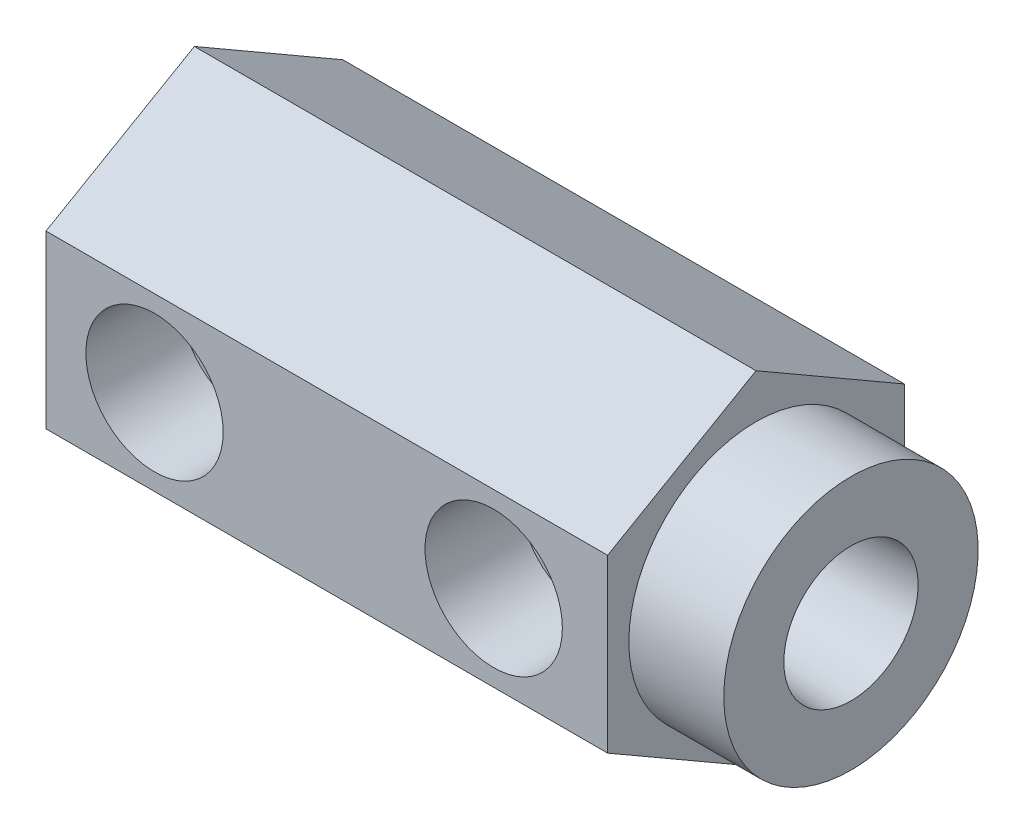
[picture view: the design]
ISO-10303-21;
HEADER;
FILE_DESCRIPTION(('STEP AP214'),'2;1');
FILE_NAME('part.step','',(''),(''),'','','');
FILE_SCHEMA(('AUTOMOTIVE_DESIGN { 1 0 10303 214 1 1 1 1 }'));
ENDSEC;
DATA;
#1=APPLICATION_CONTEXT('core data for automotive mechanical design processes');
#2=APPLICATION_PROTOCOL_DEFINITION('international standard','automotive_design',2000,#1);
#3=PRODUCT_CONTEXT('',#1,'mechanical');
#4=PRODUCT('Part','Part','',(#3));
#5=PRODUCT_RELATED_PRODUCT_CATEGORY('part','',(#4));
#6=PRODUCT_DEFINITION_FORMATION('','',#4);
#7=PRODUCT_DEFINITION_CONTEXT('part definition',#1,'design');
#8=PRODUCT_DEFINITION('design','',#6,#7);
#9=PRODUCT_DEFINITION_SHAPE('','',#8);
#10=(LENGTH_UNIT() NAMED_UNIT(*) SI_UNIT(.MILLI.,.METRE.));
#11=(NAMED_UNIT(*) PLANE_ANGLE_UNIT() SI_UNIT($,.RADIAN.));
#12=(NAMED_UNIT(*) SI_UNIT($,.STERADIAN.) SOLID_ANGLE_UNIT());
#13=UNCERTAINTY_MEASURE_WITH_UNIT(LENGTH_MEASURE(1.E-05),#10,'distance_accuracy_value','');
#14=(GEOMETRIC_REPRESENTATION_CONTEXT(3) GLOBAL_UNCERTAINTY_ASSIGNED_CONTEXT((#13)) GLOBAL_UNIT_ASSIGNED_CONTEXT((#10,
#11,#12)) REPRESENTATION_CONTEXT('',''));
#15=CARTESIAN_POINT('',(0.,0.,0.));
#16=DIRECTION('',(0.,0.,1.));
#17=DIRECTION('',(1.,0.,0.));
#18=AXIS2_PLACEMENT_3D('',#15,#16,#17);
#19=CARTESIAN_POINT('',(49.1744,0.,0.));
#20=DIRECTION('',(-1.,0.,0.));
#21=DIRECTION('',(0.,0.,1.));
#22=AXIS2_PLACEMENT_3D('',#19,#20,#21);
#23=PLANE('',#22);
#24=CARTESIAN_POINT('',(49.1744,0.,0.));
#25=DIRECTION('',(-1.,0.,0.));
#26=DIRECTION('',(0.,0.,1.));
#27=AXIS2_PLACEMENT_3D('',#24,#25,#26);
#28=CIRCLE('',#27,9.525);
#29=CARTESIAN_POINT('',(49.1744,0.,9.525));
#30=VERTEX_POINT('',#29);
#31=EDGE_CURVE('E165',#30,#30,#28,.T.);
#32=ORIENTED_EDGE('',*,*,#31,.F.);
#33=EDGE_LOOP('',(#32));
#34=FACE_BOUND('',#33,.T.);
#35=CARTESIAN_POINT('',(49.1744,0.,0.));
#36=DIRECTION('',(-1.,0.,0.));
#37=DIRECTION('',(0.,0.,1.));
#38=AXIS2_PLACEMENT_3D('',#35,#36,#37);
#39=CIRCLE('',#38,5.0292);
#40=CARTESIAN_POINT('',(49.1744,0.,5.0292));
#41=VERTEX_POINT('',#40);
#42=EDGE_CURVE('E256',#41,#41,#39,.T.);
#43=ORIENTED_EDGE('',*,*,#42,.T.);
#44=EDGE_LOOP('',(#43));
#45=FACE_BOUND('',#44,.T.);
#46=ADVANCED_FACE('F35',(#34,#45),#23,.F.);
#47=CARTESIAN_POINT('',(33.528,0.,11.1125));
#48=DIRECTION('',(0.,0.,1.));
#49=DIRECTION('',(1.,0.,0.));
#50=AXIS2_PLACEMENT_3D('',#47,#48,#49);
#51=CYLINDRICAL_SURFACE('',#50,4.2164);
#52=CARTESIAN_POINT('',(37.5572446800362,1.24226256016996,4.18846));
#53=CARTESIAN_POINT('',(37.5231998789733,1.35273524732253,4.15571145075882));
#54=CARTESIAN_POINT('',(37.4849506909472,1.46061657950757,4.11894514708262));
#55=CARTESIAN_POINT('',(37.4010204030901,1.67046449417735,4.03838194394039));
#56=CARTESIAN_POINT('',(37.3553534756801,1.77244186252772,3.99459845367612));
#57=CARTESIAN_POINT('',(37.2579636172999,1.96909195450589,3.90138657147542));
#58=CARTESIAN_POINT('',(37.2063122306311,2.06383226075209,3.85202501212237));
#59=CARTESIAN_POINT('',(37.0973370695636,2.24704879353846,3.74810382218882));
#60=CARTESIAN_POINT('',(37.040010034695,2.33552136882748,3.69354120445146));
#61=CARTESIAN_POINT('',(36.9057433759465,2.52699524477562,3.56608812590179));
#62=CARTESIAN_POINT('',(36.8274426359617,2.62823562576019,3.49198535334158));
#63=CARTESIAN_POINT('',(36.6643644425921,2.82084714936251,3.33832581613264));
#64=CARTESIAN_POINT('',(36.5795859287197,2.91221667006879,3.25876815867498));
#65=CARTESIAN_POINT('',(36.4040104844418,3.08575940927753,3.09496594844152));
#66=CARTESIAN_POINT('',(36.313183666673,3.16788058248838,3.01069851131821));
#67=CARTESIAN_POINT('',(36.1266289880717,3.32262611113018,2.83900033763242));
#68=CARTESIAN_POINT('',(36.0309017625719,3.39525169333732,2.75157001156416));
#69=CARTESIAN_POINT('',(35.8327510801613,3.53285031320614,2.57262594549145));
#70=CARTESIAN_POINT('',(35.7302251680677,3.59761324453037,2.48106457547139));
#71=CARTESIAN_POINT('',(35.5205770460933,3.7178327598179,2.29700025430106));
#72=CARTESIAN_POINT('',(35.413452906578,3.77328538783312,2.2044969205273));
#73=CARTESIAN_POINT('',(35.1946305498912,3.87490518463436,2.02052791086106));
#74=CARTESIAN_POINT('',(35.0829462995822,3.9210984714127,1.92906002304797));
#75=CARTESIAN_POINT('',(34.8537235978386,4.00442086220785,1.74949909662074));
#76=CARTESIAN_POINT('',(34.7361912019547,4.04155911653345,1.66140272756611));
#77=CARTESIAN_POINT('',(34.5288880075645,4.09683754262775,1.51866750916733));
#78=CARTESIAN_POINT('',(34.4412500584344,4.11734344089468,1.46186744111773));
#79=CARTESIAN_POINT('',(34.2602263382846,4.15335926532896,1.35613372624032));
#80=CARTESIAN_POINT('',(34.166846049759,4.16887387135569,1.30719273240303));
#81=CARTESIAN_POINT('',(34.0032271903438,4.19006857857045,1.23719318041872));
#82=CARTESIAN_POINT('',(33.9349286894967,4.19730703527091,1.21220489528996));
#83=CARTESIAN_POINT('',(33.7951867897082,4.20850549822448,1.17274151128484));
#84=CARTESIAN_POINT('',(33.7237554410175,4.21247707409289,1.15822933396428));
#85=CARTESIAN_POINT('',(33.5783648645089,4.21673052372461,1.14266473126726));
#86=CARTESIAN_POINT('',(33.5043857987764,4.21696850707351,1.14177241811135));
#87=CARTESIAN_POINT('',(33.3576831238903,4.21360126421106,1.15412545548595));
#88=CARTESIAN_POINT('',(33.2849618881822,4.20998943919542,1.16739508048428));
#89=CARTESIAN_POINT('',(33.1190041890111,4.19759986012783,1.21128529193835));
#90=CARTESIAN_POINT('',(33.0270782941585,4.187494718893,1.24623585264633));
#91=CARTESIAN_POINT('',(32.8490963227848,4.16236327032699,1.32777375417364));
#92=CARTESIAN_POINT('',(32.7630740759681,4.14731106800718,1.37442201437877));
#93=CARTESIAN_POINT('',(32.5528728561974,4.10412945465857,1.49961321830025));
#94=CARTESIAN_POINT('',(32.4317509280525,4.07325238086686,1.58224397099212));
#95=CARTESIAN_POINT('',(32.1964925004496,4.00252087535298,1.75355286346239));
#96=CARTESIAN_POINT('',(32.082370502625,3.96264855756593,1.8422428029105));
#97=CARTESIAN_POINT('',(31.8591995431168,3.87396052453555,2.02210861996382));
#98=CARTESIAN_POINT('',(31.7501633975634,3.8251236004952,2.11328994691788));
#99=CARTESIAN_POINT('',(31.5367944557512,3.71851194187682,2.29570274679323));
#100=CARTESIAN_POINT('',(31.4324577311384,3.66074485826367,2.38693411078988));
#101=CARTESIAN_POINT('',(31.2217376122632,3.5320493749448,2.57385350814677));
#102=CARTESIAN_POINT('',(31.1156451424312,3.46051807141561,2.66945656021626));
#103=CARTESIAN_POINT('',(30.9087479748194,3.30668578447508,2.85780367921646));
#104=CARTESIAN_POINT('',(30.8079452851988,3.22438075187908,2.95054665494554));
#105=CARTESIAN_POINT('',(30.6125764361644,3.04885609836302,3.13157084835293));
#106=CARTESIAN_POINT('',(30.5179955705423,2.95566377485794,3.21986246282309));
#107=CARTESIAN_POINT('',(30.3358368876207,2.7579369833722,3.39076686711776));
#108=CARTESIAN_POINT('',(30.248259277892,2.65340217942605,3.47337948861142));
#109=CARTESIAN_POINT('',(30.0468993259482,2.38706899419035,3.66401417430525));
#110=CARTESIAN_POINT('',(29.9372028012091,2.21943248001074,3.76846671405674));
#111=CARTESIAN_POINT('',(29.7890253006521,1.95153796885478,3.91000109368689));
#112=CARTESIAN_POINT('',(29.742405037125,1.85961524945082,3.95461240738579));
#113=CARTESIAN_POINT('',(29.6552306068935,1.67047982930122,4.03813946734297));
#114=CARTESIAN_POINT('',(29.6146718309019,1.57327122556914,4.07705954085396));
#115=CARTESIAN_POINT('',(29.5633807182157,1.43577933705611,4.12632709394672));
#116=CARTESIAN_POINT('',(29.5497360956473,1.3975361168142,4.13943898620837));
#117=CARTESIAN_POINT('',(29.5234701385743,1.32038947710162,4.16468855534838));
#118=CARTESIAN_POINT('',(29.510848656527,1.28148615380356,4.17682637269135));
#119=CARTESIAN_POINT('',(29.4987553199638,1.24226256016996,4.18846));
#120=B_SPLINE_CURVE_WITH_KNOTS('',3,(#52,#53,#54,#55,#56,#57,#58,#59,#60,#61,#62,#63,#64,#65,
#66,#67,#68,#69,#70,#71,#72,#73,#74,#75,#76,#77,#78,#79,#80,#81,#82,#83,#84,#85,#86,#87,#88,#89,
#90,#91,#92,#93,#94,#95,#96,#97,#98,#99,#100,#101,#102,#103,#104,#105,#106,#107,#108,#109,#110,
#111,#112,#113,#114,#115,#116,#117,#118,#119),.UNSPECIFIED.,.F.,.F.,(4,2,2,2,2,2,2,2,2,2,2,2,2,
2,2,2,2,2,2,2,2,2,2,2,2,2,2,2,2,2,2,2,2,4),(0.,0.360139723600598,0.719599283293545,
1.07513522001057,1.43087659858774,1.87389656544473,2.31698921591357,2.76246242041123,
3.2078780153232,3.6633626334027,4.11904029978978,4.57341395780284,5.02732654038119,
5.34631244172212,5.66499838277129,5.88362011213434,6.10146422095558,6.32186731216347,
6.54264879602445,6.83756415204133,7.13404848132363,7.58258817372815,8.03202772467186,
8.48254461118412,8.93267763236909,9.41140117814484,9.89030516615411,10.3680331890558,
10.8457753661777,11.5205176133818,11.8571135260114,12.1934521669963,12.3214366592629,
12.4494026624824),.UNSPECIFIED.);
#121=CARTESIAN_POINT('',(37.5572446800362,1.24226256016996,4.18846));
#122=VERTEX_POINT('',#121);
#123=CARTESIAN_POINT('',(29.4987553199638,1.24226256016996,4.18846));
#124=VERTEX_POINT('',#123);
#125=EDGE_CURVE('E281',#122,#124,#120,.T.);
#126=ORIENTED_EDGE('',*,*,#125,.F.);
#127=CARTESIAN_POINT('',(33.528,0.,4.18846));
#128=DIRECTION('',(0.,0.,1.));
#129=DIRECTION('',(1.,0.,0.));
#130=AXIS2_PLACEMENT_3D('',#127,#128,#129);
#131=CIRCLE('',#130,4.2164);
#132=EDGE_CURVE('E159',#122,#124,#131,.T.);
#133=ORIENTED_EDGE('',*,*,#132,.T.);
#134=EDGE_LOOP('',(#126,#133));
#135=FACE_BOUND('',#134,.T.);
#136=ADVANCED_FACE('F290',(#135),#51,.F.);
#137=CARTESIAN_POINT('',(29.4987553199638,-1.24226256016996,4.18846));
#138=CARTESIAN_POINT('',(29.5328001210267,-1.35273524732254,4.15571145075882));
#139=CARTESIAN_POINT('',(29.5710493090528,-1.46061657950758,4.11894514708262));
#140=CARTESIAN_POINT('',(29.6549795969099,-1.67046449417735,4.03838194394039));
#141=CARTESIAN_POINT('',(29.7006465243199,-1.77244186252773,3.99459845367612));
#142=CARTESIAN_POINT('',(29.7980363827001,-1.96909195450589,3.90138657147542));
#143=CARTESIAN_POINT('',(29.8496877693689,-2.0638322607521,3.85202501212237));
#144=CARTESIAN_POINT('',(29.9586629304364,-2.24704879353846,3.74810382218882));
#145=CARTESIAN_POINT('',(30.015989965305,-2.33552136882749,3.69354120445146));
#146=CARTESIAN_POINT('',(30.1502566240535,-2.52699524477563,3.56608812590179));
#147=CARTESIAN_POINT('',(30.2285573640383,-2.6282356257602,3.49198535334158));
#148=CARTESIAN_POINT('',(30.3916355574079,-2.82084714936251,3.33832581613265));
#149=CARTESIAN_POINT('',(30.4764140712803,-2.9122166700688,3.25876815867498));
#150=CARTESIAN_POINT('',(30.6519895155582,-3.08575940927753,3.09496594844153));
#151=CARTESIAN_POINT('',(30.742816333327,-3.16788058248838,3.01069851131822));
#152=CARTESIAN_POINT('',(30.9293710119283,-3.32262611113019,2.83900033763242));
#153=CARTESIAN_POINT('',(31.0250982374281,-3.39525169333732,2.75157001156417));
#154=CARTESIAN_POINT('',(31.2232489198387,-3.53285031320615,2.57262594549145));
#155=CARTESIAN_POINT('',(31.3257748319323,-3.59761324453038,2.48106457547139));
#156=CARTESIAN_POINT('',(31.5354229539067,-3.7178327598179,2.29700025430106));
#157=CARTESIAN_POINT('',(31.642547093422,-3.77328538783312,2.2044969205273));
#158=CARTESIAN_POINT('',(31.8613694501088,-3.87490518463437,2.02052791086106));
#159=CARTESIAN_POINT('',(31.9730537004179,-3.9210984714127,1.92906002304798));
#160=CARTESIAN_POINT('',(32.2022764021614,-4.00442086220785,1.74949909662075));
#161=CARTESIAN_POINT('',(32.3198087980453,-4.04155911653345,1.66140272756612));
#162=CARTESIAN_POINT('',(32.5271119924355,-4.09683754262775,1.51866750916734));
#163=CARTESIAN_POINT('',(32.6147499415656,-4.11734344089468,1.46186744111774));
#164=CARTESIAN_POINT('',(32.7957736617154,-4.15335926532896,1.35613372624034));
#165=CARTESIAN_POINT('',(32.889153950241,-4.16887387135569,1.30719273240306));
#166=CARTESIAN_POINT('',(33.0527728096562,-4.19006857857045,1.23719318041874));
#167=CARTESIAN_POINT('',(33.1210713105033,-4.19730703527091,1.21220489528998));
#168=CARTESIAN_POINT('',(33.2608132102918,-4.20850549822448,1.17274151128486));
#169=CARTESIAN_POINT('',(33.3322445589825,-4.21247707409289,1.15822933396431));
#170=CARTESIAN_POINT('',(33.4776351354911,-4.21673052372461,1.14266473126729));
#171=CARTESIAN_POINT('',(33.5516142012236,-4.21696850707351,1.14177241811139));
#172=CARTESIAN_POINT('',(33.6983168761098,-4.21360126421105,1.15412545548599));
#173=CARTESIAN_POINT('',(33.7710381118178,-4.20998943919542,1.16739508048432));
#174=CARTESIAN_POINT('',(33.9369958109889,-4.19759986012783,1.21128529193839));
#175=CARTESIAN_POINT('',(34.0289217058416,-4.187494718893,1.24623585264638));
#176=CARTESIAN_POINT('',(34.2069036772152,-4.16236327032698,1.3277737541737));
#177=CARTESIAN_POINT('',(34.292925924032,-4.14731106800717,1.37442201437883));
#178=CARTESIAN_POINT('',(34.5031271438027,-4.10412945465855,1.49961321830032));
#179=CARTESIAN_POINT('',(34.6242490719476,-4.07325238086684,1.5822439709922));
#180=CARTESIAN_POINT('',(34.8595074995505,-4.00252087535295,1.75355286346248));
#181=CARTESIAN_POINT('',(34.9736294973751,-3.9626485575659,1.8422428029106));
#182=CARTESIAN_POINT('',(35.1968004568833,-3.8739605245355,2.02210861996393));
#183=CARTESIAN_POINT('',(35.3058366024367,-3.82512360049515,2.11328994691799));
#184=CARTESIAN_POINT('',(35.5192055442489,-3.71851194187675,2.29570274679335));
#185=CARTESIAN_POINT('',(35.6235422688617,-3.6607448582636,2.38693411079));
#186=CARTESIAN_POINT('',(35.8342623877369,-3.53204937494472,2.5738535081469));
#187=CARTESIAN_POINT('',(35.940354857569,-3.46051807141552,2.66945656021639));
#188=CARTESIAN_POINT('',(36.1472520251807,-3.30668578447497,2.85780367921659));
#189=CARTESIAN_POINT('',(36.2480547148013,-3.22438075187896,2.95054665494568));
#190=CARTESIAN_POINT('',(36.4434235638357,-3.04885609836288,3.13157084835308));
#191=CARTESIAN_POINT('',(36.5380044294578,-2.95566377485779,3.21986246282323));
#192=CARTESIAN_POINT('',(36.7201631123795,-2.75793698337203,3.3907668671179));
#193=CARTESIAN_POINT('',(36.8077407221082,-2.65340217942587,3.47337948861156));
#194=CARTESIAN_POINT('',(37.0091006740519,-2.38706899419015,3.66401417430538));
#195=CARTESIAN_POINT('',(37.118797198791,-2.21943248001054,3.76846671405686));
#196=CARTESIAN_POINT('',(37.2669746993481,-1.95153796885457,3.910001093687));
#197=CARTESIAN_POINT('',(37.3135949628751,-1.85961524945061,3.95461240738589));
#198=CARTESIAN_POINT('',(37.4007693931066,-1.67047982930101,4.03813946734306));
#199=CARTESIAN_POINT('',(37.4413281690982,-1.57327122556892,4.07705954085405));
#200=CARTESIAN_POINT('',(37.4926192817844,-1.43577933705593,4.12632709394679));
#201=CARTESIAN_POINT('',(37.5062639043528,-1.39753611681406,4.13943898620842));
#202=CARTESIAN_POINT('',(37.5325298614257,-1.32038947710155,4.1646885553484));
#203=CARTESIAN_POINT('',(37.545151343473,-1.28148615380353,4.17682637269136));
#204=CARTESIAN_POINT('',(37.5572446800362,-1.24226256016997,4.18846));
#205=B_SPLINE_CURVE_WITH_KNOTS('',3,(#137,#138,#139,#140,#141,#142,#143,#144,#145,#146,#147,
#148,#149,#150,#151,#152,#153,#154,#155,#156,#157,#158,#159,#160,#161,#162,#163,#164,#165,#166,
#167,#168,#169,#170,#171,#172,#173,#174,#175,#176,#177,#178,#179,#180,#181,#182,#183,#184,#185,
#186,#187,#188,#189,#190,#191,#192,#193,#194,#195,#196,#197,#198,#199,#200,#201,#202,#203,#204),
.UNSPECIFIED.,.F.,.F.,(4,2,2,2,2,2,2,2,2,2,2,2,2,2,2,2,2,2,2,2,2,2,2,2,2,2,2,2,2,2,2,2,2,4),(0.,
0.360139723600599,0.719599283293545,1.07513522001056,1.43087659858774,1.87389656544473,
2.31698921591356,2.76246242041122,3.2078780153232,3.6633626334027,4.11904029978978,
4.57341395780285,5.02732654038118,5.34631244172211,5.66499838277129,5.88362011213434,
6.10146422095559,6.32186731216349,6.54264879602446,6.83756415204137,7.13404848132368,
7.58258817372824,8.03202772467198,8.48254461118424,8.93267763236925,9.41140117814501,
9.89030516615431,10.3680331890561,10.8457753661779,11.520517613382,11.8571135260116,
12.1934521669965,12.321436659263,12.4494026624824),.UNSPECIFIED.);
#206=CARTESIAN_POINT('',(29.4987553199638,-1.24226256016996,4.18846));
#207=VERTEX_POINT('',#206);
#208=CARTESIAN_POINT('',(37.5572446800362,-1.24226256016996,4.18846));
#209=VERTEX_POINT('',#208);
#210=EDGE_CURVE('E146',#207,#209,#205,.T.);
#211=ORIENTED_EDGE('',*,*,#210,.F.);
#212=EDGE_CURVE('E145',#207,#209,#131,.T.);
#213=ORIENTED_EDGE('',*,*,#212,.T.);
#214=EDGE_LOOP('',(#211,#213));
#215=FACE_BOUND('',#214,.T.);
#216=ADVANCED_FACE('F294',(#215),#51,.F.);
#217=CARTESIAN_POINT('',(37.7444,0.,4.18846));
#218=DIRECTION('',(0.,0.,-1.));
#219=DIRECTION('',(-1.,0.,0.));
#220=AXIS2_PLACEMENT_3D('',#217,#218,#219);
#221=PLANE('',#220);
#222=DIRECTION('',(-1.,0.,0.));
#223=VECTOR('',#222,1.);
#224=CARTESIAN_POINT('',(0.,-1.24226256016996,4.18846));
#225=LINE('',#224,#223);
#226=CARTESIAN_POINT('',(28.7506884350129,-1.24226256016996,4.18846));
#227=VERTEX_POINT('',#226);
#228=EDGE_CURVE('E131',#227,#207,#225,.F.);
#229=ORIENTED_EDGE('',*,*,#228,.F.);
#230=CARTESIAN_POINT('',(33.528,0.,4.18846));
#231=DIRECTION('',(0.,0.,1.));
#232=DIRECTION('',(1.,0.,0.));
#233=AXIS2_PLACEMENT_3D('',#230,#231,#232);
#234=CIRCLE('',#233,4.93618496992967);
#235=CARTESIAN_POINT('',(38.3053115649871,-1.24226256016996,4.18846));
#236=VERTEX_POINT('',#235);
#237=EDGE_CURVE('E143',#227,#236,#234,.T.);
#238=ORIENTED_EDGE('',*,*,#237,.T.);
#239=EDGE_CURVE('E148',#209,#236,#225,.F.);
#240=ORIENTED_EDGE('',*,*,#239,.F.);
#241=ORIENTED_EDGE('',*,*,#212,.F.);
#242=EDGE_LOOP('',(#229,#238,#240,#241));
#243=FACE_BOUND('',#242,.T.);
#244=ADVANCED_FACE('F141',(#243),#221,.F.);
#245=DIRECTION('',(-1.,0.,0.));
#246=VECTOR('',#245,1.);
#247=CARTESIAN_POINT('',(0.,1.24226256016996,4.18846));
#248=LINE('',#247,#246);
#249=CARTESIAN_POINT('',(38.3053115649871,1.24226256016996,4.18846));
#250=VERTEX_POINT('',#249);
#251=EDGE_CURVE('E285',#250,#122,#248,.T.);
#252=ORIENTED_EDGE('',*,*,#251,.F.);
#253=CARTESIAN_POINT('',(28.7506884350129,1.24226256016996,4.18846));
#254=VERTEX_POINT('',#253);
#255=EDGE_CURVE('E151',#250,#254,#234,.T.);
#256=ORIENTED_EDGE('',*,*,#255,.T.);
#257=EDGE_CURVE('E55',#124,#254,#248,.T.);
#258=ORIENTED_EDGE('',*,*,#257,.F.);
#259=ORIENTED_EDGE('',*,*,#132,.F.);
#260=EDGE_LOOP('',(#252,#256,#258,#259));
#261=FACE_BOUND('',#260,.T.);
#262=ADVANCED_FACE('F372',(#261),#221,.F.);
#263=CARTESIAN_POINT('',(33.528,0.,11.1125));
#264=DIRECTION('',(0.,0.,1.));
#265=DIRECTION('',(1.,0.,0.));
#266=AXIS2_PLACEMENT_3D('',#263,#264,#265);
#267=CONICAL_SURFACE('',#266,5.1435,0.0299323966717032);
#268=CARTESIAN_POINT('',(33.528,0.,11.1125));
#269=DIRECTION('',(0.,0.,1.));
#270=DIRECTION('',(1.,0.,0.));
#271=AXIS2_PLACEMENT_3D('',#268,#269,#270);
#272=CIRCLE('',#271,5.1435);
#273=CARTESIAN_POINT('',(38.6715,0.,11.1125));
#274=VERTEX_POINT('',#273);
#275=EDGE_CURVE('E152',#274,#274,#272,.T.);
#276=ORIENTED_EDGE('',*,*,#275,.T.);
#277=EDGE_LOOP('',(#276));
#278=FACE_BOUND('',#277,.T.);
#279=CARTESIAN_POINT('',(38.3051300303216,-1.24293668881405,4.18826));
#280=CARTESIAN_POINT('',(38.3286071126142,-1.15583523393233,4.21412336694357));
#281=CARTESIAN_POINT('',(38.3497868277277,-1.06732839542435,4.23741836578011));
#282=CARTESIAN_POINT('',(38.3872560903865,-0.888007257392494,4.27858516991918));
#283=CARTESIAN_POINT('',(38.4035434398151,-0.797191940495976,4.29645453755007));
#284=CARTESIAN_POINT('',(38.4309049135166,-0.613876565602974,4.32645329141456));
#285=CARTESIAN_POINT('',(38.4419813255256,-0.521377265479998,4.33858519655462));
#286=CARTESIAN_POINT('',(38.4587218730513,-0.335324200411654,4.35691457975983));
#287=CARTESIAN_POINT('',(38.4643871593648,-0.241770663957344,4.36311331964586));
#288=CARTESIAN_POINT('',(38.4702050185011,-0.0540097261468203,4.36947895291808));
#289=CARTESIAN_POINT('',(38.470341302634,0.0401987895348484,4.36962802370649));
#290=CARTESIAN_POINT('',(38.4650571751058,0.22827319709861,4.36384645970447));
#291=CARTESIAN_POINT('',(38.459636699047,0.322139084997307,4.35791575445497));
#292=CARTESIAN_POINT('',(38.4433617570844,0.508659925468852,4.34009705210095));
#293=CARTESIAN_POINT('',(38.4325165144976,0.601316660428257,4.32821916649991));
#294=CARTESIAN_POINT('',(38.4056075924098,0.784900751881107,4.29871858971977));
#295=CARTESIAN_POINT('',(38.3895464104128,0.875828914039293,4.28109864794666));
#296=CARTESIAN_POINT('',(38.3613463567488,1.01252796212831,4.25011977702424));
#297=CARTESIAN_POINT('',(38.3509951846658,1.05913454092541,4.23874207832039));
#298=CARTESIAN_POINT('',(38.3290123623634,1.15159574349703,4.21456055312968));
#299=CARTESIAN_POINT('',(38.3173825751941,1.19745135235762,4.20175880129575));
#300=CARTESIAN_POINT('',(38.3051300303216,1.24293668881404,4.18826));
#301=B_SPLINE_CURVE_WITH_KNOTS('',3,(#279,#280,#281,#282,#283,#284,#285,#286,#287,#288,#289,
#290,#291,#292,#293,#294,#295,#296,#297,#298,#299,#300),.UNSPECIFIED.,.F.,.F.,(4,2,2,2,2,2,2,2,
2,2,4),(0.,0.281492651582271,0.563111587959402,0.844606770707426,1.12604207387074,
1.40830643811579,1.69057407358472,1.97236341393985,2.25401802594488,2.40121826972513,
2.54820680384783),.UNSPECIFIED.);
#302=EDGE_CURVE('E11',#236,#250,#301,.T.);
#303=ORIENTED_EDGE('',*,*,#302,.F.);
#304=ORIENTED_EDGE('',*,*,#237,.F.);
#305=CARTESIAN_POINT('',(28.7508699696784,1.24293668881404,4.18826));
#306=CARTESIAN_POINT('',(28.7273928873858,1.15583523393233,4.21412336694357));
#307=CARTESIAN_POINT('',(28.7062131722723,1.06732839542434,4.23741836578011));
#308=CARTESIAN_POINT('',(28.6687439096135,0.888007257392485,4.27858516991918));
#309=CARTESIAN_POINT('',(28.6524565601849,0.797191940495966,4.29645453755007));
#310=CARTESIAN_POINT('',(28.6250950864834,0.613876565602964,4.32645329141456));
#311=CARTESIAN_POINT('',(28.6140186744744,0.521377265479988,4.33858519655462));
#312=CARTESIAN_POINT('',(28.5972781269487,0.335324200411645,4.35691457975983));
#313=CARTESIAN_POINT('',(28.5916128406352,0.241770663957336,4.36311331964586));
#314=CARTESIAN_POINT('',(28.5857949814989,0.0540097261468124,4.36947895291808));
#315=CARTESIAN_POINT('',(28.585658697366,-0.0401987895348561,4.36962802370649));
#316=CARTESIAN_POINT('',(28.5909428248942,-0.228273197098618,4.36384645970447));
#317=CARTESIAN_POINT('',(28.596363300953,-0.322139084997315,4.35791575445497));
#318=CARTESIAN_POINT('',(28.6126382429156,-0.50865992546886,4.34009705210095));
#319=CARTESIAN_POINT('',(28.6234834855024,-0.601316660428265,4.32821916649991));
#320=CARTESIAN_POINT('',(28.6503924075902,-0.784900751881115,4.29871858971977));
#321=CARTESIAN_POINT('',(28.6664535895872,-0.875828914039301,4.28109864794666));
#322=CARTESIAN_POINT('',(28.6946536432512,-1.01252796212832,4.25011977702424));
#323=CARTESIAN_POINT('',(28.7050048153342,-1.05913454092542,4.23874207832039));
#324=CARTESIAN_POINT('',(28.7269876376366,-1.15159574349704,4.21456055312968));
#325=CARTESIAN_POINT('',(28.738617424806,-1.19745135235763,4.20175880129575));
#326=CARTESIAN_POINT('',(28.7508699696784,-1.24293668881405,4.18826));
#327=B_SPLINE_CURVE_WITH_KNOTS('',3,(#305,#306,#307,#308,#309,#310,#311,#312,#313,#314,#315,
#316,#317,#318,#319,#320,#321,#322,#323,#324,#325,#326),.UNSPECIFIED.,.F.,.F.,(4,2,2,2,2,2,2,2,
2,2,4),(0.,0.281492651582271,0.563111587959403,0.844606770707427,1.12604207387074,
1.40830643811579,1.69057407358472,1.97236341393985,2.25401802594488,2.40121826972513,
2.54820680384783),.UNSPECIFIED.);
#328=EDGE_CURVE('E48',#254,#227,#327,.T.);
#329=ORIENTED_EDGE('',*,*,#328,.F.);
#330=ORIENTED_EDGE('',*,*,#255,.F.);
#331=EDGE_LOOP('',(#303,#304,#329,#330));
#332=FACE_BOUND('',#331,.T.);
#333=ADVANCED_FACE('F150',(#278,#332),#267,.F.);
#334=CARTESIAN_POINT('',(49.1744,0.,0.));
#335=DIRECTION('',(1.,0.,0.));
#336=DIRECTION('',(0.,0.,-1.));
#337=AXIS2_PLACEMENT_3D('',#334,#335,#336);
#338=CYLINDRICAL_SURFACE('',#337,3.175);
#339=CARTESIAN_POINT('',(19.2024,0.,0.));
#340=DIRECTION('',(1.,0.,0.));
#341=DIRECTION('',(0.,0.,-1.));
#342=AXIS2_PLACEMENT_3D('',#339,#340,#341);
#343=CIRCLE('',#342,3.17499999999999);
#344=CARTESIAN_POINT('',(19.2024,0.,-3.17499999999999));
#345=VERTEX_POINT('',#344);
#346=EDGE_CURVE('E611',#345,#345,#343,.T.);
#347=ORIENTED_EDGE('',*,*,#346,.F.);
#348=EDGE_LOOP('',(#347));
#349=FACE_BOUND('',#348,.T.);
#350=CARTESIAN_POINT('',(26.9494,0.,0.));
#351=DIRECTION('',(1.,0.,0.));
#352=DIRECTION('',(0.,0.,-1.));
#353=AXIS2_PLACEMENT_3D('',#350,#351,#352);
#354=CIRCLE('',#353,3.175);
#355=CARTESIAN_POINT('',(26.9494,0.,-3.17499999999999));
#356=VERTEX_POINT('',#355);
#357=EDGE_CURVE('E254',#356,#356,#354,.F.);
#358=ORIENTED_EDGE('',*,*,#357,.F.);
#359=EDGE_LOOP('',(#358));
#360=FACE_BOUND('',#359,.T.);
#361=ADVANCED_FACE('F339',(#349,#360),#338,.F.);
#362=CARTESIAN_POINT('',(42.0624,6.41580486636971,11.1125));
#363=DIRECTION('',(0.,0.,-1.));
#364=DIRECTION('',(0.,1.,0.));
#365=AXIS2_PLACEMENT_3D('',#362,#363,#364);
#366=PLANE('',#365);
#367=CARTESIAN_POINT('',(8.128,0.,11.1125));
#368=DIRECTION('',(0.,0.,1.));
#369=DIRECTION('',(1.,0.,0.));
#370=AXIS2_PLACEMENT_3D('',#367,#368,#369);
#371=CIRCLE('',#370,5.1435);
#372=CARTESIAN_POINT('',(13.2715,0.,11.1125));
#373=VERTEX_POINT('',#372);
#374=EDGE_CURVE('E368',#373,#373,#371,.T.);
#375=ORIENTED_EDGE('',*,*,#374,.F.);
#376=EDGE_LOOP('',(#375));
#377=FACE_BOUND('',#376,.T.);
#378=ORIENTED_EDGE('',*,*,#275,.F.);
#379=EDGE_LOOP('',(#378));
#380=FACE_BOUND('',#379,.T.);
#381=DIRECTION('',(0.,-1.,0.));
#382=VECTOR('',#381,1.);
#383=CARTESIAN_POINT('',(0.,6.41580486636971,11.1125));
#384=LINE('',#383,#382);
#385=CARTESIAN_POINT('',(0.,6.41580486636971,11.1125));
#386=VERTEX_POINT('',#385);
#387=CARTESIAN_POINT('',(0.,-6.41580486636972,11.1125));
#388=VERTEX_POINT('',#387);
#389=EDGE_CURVE('E168',#386,#388,#384,.T.);
#390=ORIENTED_EDGE('',*,*,#389,.T.);
#391=DIRECTION('',(-1.,0.,0.));
#392=VECTOR('',#391,1.);
#393=CARTESIAN_POINT('',(42.0624,-6.41580486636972,11.1125));
#394=LINE('',#393,#392);
#395=CARTESIAN_POINT('',(42.0624,-6.41580486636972,11.1125));
#396=VERTEX_POINT('',#395);
#397=EDGE_CURVE('E173',#396,#388,#394,.T.);
#398=ORIENTED_EDGE('',*,*,#397,.F.);
#399=DIRECTION('',(0.,-1.,0.));
#400=VECTOR('',#399,1.);
#401=CARTESIAN_POINT('',(42.0624,6.41580486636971,11.1125));
#402=LINE('',#401,#400);
#403=CARTESIAN_POINT('',(42.0624,6.41580486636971,11.1125));
#404=VERTEX_POINT('',#403);
#405=EDGE_CURVE('E174',#404,#396,#402,.T.);
#406=ORIENTED_EDGE('',*,*,#405,.F.);
#407=DIRECTION('',(-1.,0.,0.));
#408=VECTOR('',#407,1.);
#409=CARTESIAN_POINT('',(42.0624,6.41580486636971,11.1125));
#410=LINE('',#409,#408);
#411=EDGE_CURVE('E188',#404,#386,#410,.T.);
#412=ORIENTED_EDGE('',*,*,#411,.T.);
#413=EDGE_LOOP('',(#390,#398,#406,#412));
#414=FACE_BOUND('',#413,.T.);
#415=ADVANCED_FACE('F37',(#377,#380,#414),#366,.F.);
#416=CARTESIAN_POINT('',(42.0624,-6.41580486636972,11.1125));
#417=DIRECTION('',(0.,0.866025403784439,-0.5));
#418=DIRECTION('',(0.,0.5,0.866025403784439));
#419=AXIS2_PLACEMENT_3D('',#416,#417,#418);
#420=PLANE('',#419);
#421=DIRECTION('',(0.,-0.5,-0.866025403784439));
#422=VECTOR('',#421,1.);
#423=CARTESIAN_POINT('',(0.,-6.41580486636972,11.1125));
#424=LINE('',#423,#422);
#425=CARTESIAN_POINT('',(0.,-12.8316097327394,0.));
#426=VERTEX_POINT('',#425);
#427=EDGE_CURVE('E191',#388,#426,#424,.T.);
#428=ORIENTED_EDGE('',*,*,#427,.T.);
#429=DIRECTION('',(-1.,0.,0.));
#430=VECTOR('',#429,1.);
#431=CARTESIAN_POINT('',(42.0624,-12.8316097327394,0.));
#432=LINE('',#431,#430);
#433=CARTESIAN_POINT('',(42.0624,-12.8316097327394,0.));
#434=VERTEX_POINT('',#433);
#435=EDGE_CURVE('E211',#434,#426,#432,.T.);
#436=ORIENTED_EDGE('',*,*,#435,.F.);
#437=DIRECTION('',(0.,-0.5,-0.866025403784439));
#438=VECTOR('',#437,1.);
#439=CARTESIAN_POINT('',(42.0624,-6.41580486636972,11.1125));
#440=LINE('',#439,#438);
#441=EDGE_CURVE('E177',#396,#434,#440,.T.);
#442=ORIENTED_EDGE('',*,*,#441,.F.);
#443=ORIENTED_EDGE('',*,*,#397,.T.);
#444=EDGE_LOOP('',(#428,#436,#442,#443));
#445=FACE_BOUND('',#444,.T.);
#446=ADVANCED_FACE('F332',(#445),#420,.F.);
#447=CARTESIAN_POINT('',(42.0624,-12.8316097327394,0.));
#448=DIRECTION('',(0.,0.866025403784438,0.5));
#449=DIRECTION('',(0.,-0.5,0.866025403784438));
#450=AXIS2_PLACEMENT_3D('',#447,#448,#449);
#451=PLANE('',#450);
#452=DIRECTION('',(0.,0.5,-0.866025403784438));
#453=VECTOR('',#452,1.);
#454=CARTESIAN_POINT('',(0.,-12.8316097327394,0.));
#455=LINE('',#454,#453);
#456=CARTESIAN_POINT('',(0.,-6.41580486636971,-11.1125));
#457=VERTEX_POINT('',#456);
#458=EDGE_CURVE('E193',#426,#457,#455,.T.);
#459=ORIENTED_EDGE('',*,*,#458,.T.);
#460=DIRECTION('',(-1.,0.,0.));
#461=VECTOR('',#460,1.);
#462=CARTESIAN_POINT('',(42.0624,-6.41580486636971,-11.1125));
#463=LINE('',#462,#461);
#464=CARTESIAN_POINT('',(42.0624,-6.41580486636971,-11.1125));
#465=VERTEX_POINT('',#464);
#466=EDGE_CURVE('E208',#465,#457,#463,.T.);
#467=ORIENTED_EDGE('',*,*,#466,.F.);
#468=DIRECTION('',(0.,0.5,-0.866025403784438));
#469=VECTOR('',#468,1.);
#470=CARTESIAN_POINT('',(42.0624,-12.8316097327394,0.));
#471=LINE('',#470,#469);
#472=EDGE_CURVE('E180',#434,#465,#471,.T.);
#473=ORIENTED_EDGE('',*,*,#472,.F.);
#474=ORIENTED_EDGE('',*,*,#435,.T.);
#475=EDGE_LOOP('',(#459,#467,#473,#474));
#476=FACE_BOUND('',#475,.T.);
#477=ADVANCED_FACE('F329',(#476),#451,.F.);
#478=CARTESIAN_POINT('',(42.0624,-6.41580486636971,-11.1125));
#479=DIRECTION('',(0.,0.,1.));
#480=DIRECTION('',(1.,0.,0.));
#481=AXIS2_PLACEMENT_3D('',#478,#479,#480);
#482=PLANE('',#481);
#483=CARTESIAN_POINT('',(8.128,0.,-11.1125));
#484=DIRECTION('',(0.,0.,-1.));
#485=DIRECTION('',(-1.,0.,0.));
#486=AXIS2_PLACEMENT_3D('',#483,#484,#485);
#487=CIRCLE('',#486,5.1435);
#488=CARTESIAN_POINT('',(2.9845,0.,-11.1125));
#489=VERTEX_POINT('',#488);
#490=EDGE_CURVE('E586',#489,#489,#487,.T.);
#491=ORIENTED_EDGE('',*,*,#490,.F.);
#492=EDGE_LOOP('',(#491));
#493=FACE_BOUND('',#492,.T.);
#494=DIRECTION('',(0.,1.,0.));
#495=VECTOR('',#494,1.);
#496=CARTESIAN_POINT('',(0.,-6.41580486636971,-11.1125));
#497=LINE('',#496,#495);
#498=CARTESIAN_POINT('',(0.,6.41580486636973,-11.1125));
#499=VERTEX_POINT('',#498);
#500=EDGE_CURVE('E195',#457,#499,#497,.T.);
#501=ORIENTED_EDGE('',*,*,#500,.T.);
#502=DIRECTION('',(-1.,0.,0.));
#503=VECTOR('',#502,1.);
#504=CARTESIAN_POINT('',(42.0624,6.41580486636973,-11.1125));
#505=LINE('',#504,#503);
#506=CARTESIAN_POINT('',(42.0624,6.41580486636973,-11.1125));
#507=VERTEX_POINT('',#506);
#508=EDGE_CURVE('E205',#507,#499,#505,.T.);
#509=ORIENTED_EDGE('',*,*,#508,.F.);
#510=DIRECTION('',(0.,1.,0.));
#511=VECTOR('',#510,1.);
#512=CARTESIAN_POINT('',(42.0624,-6.41580486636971,-11.1125));
#513=LINE('',#512,#511);
#514=EDGE_CURVE('E182',#465,#507,#513,.T.);
#515=ORIENTED_EDGE('',*,*,#514,.F.);
#516=ORIENTED_EDGE('',*,*,#466,.T.);
#517=EDGE_LOOP('',(#501,#509,#515,#516));
#518=FACE_BOUND('',#517,.T.);
#519=ADVANCED_FACE('F325',(#493,#518),#482,.F.);
#520=CARTESIAN_POINT('',(42.0624,6.41580486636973,-11.1125));
#521=DIRECTION('',(0.,-0.866025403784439,0.5));
#522=DIRECTION('',(0.,-0.5,-0.866025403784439));
#523=AXIS2_PLACEMENT_3D('',#520,#521,#522);
#524=PLANE('',#523);
#525=DIRECTION('',(0.,0.5,0.866025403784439));
#526=VECTOR('',#525,1.);
#527=CARTESIAN_POINT('',(0.,6.41580486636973,-11.1125));
#528=LINE('',#527,#526);
#529=CARTESIAN_POINT('',(0.,12.8316097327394,0.));
#530=VERTEX_POINT('',#529);
#531=EDGE_CURVE('E197',#499,#530,#528,.T.);
#532=ORIENTED_EDGE('',*,*,#531,.T.);
#533=DIRECTION('',(-1.,0.,0.));
#534=VECTOR('',#533,1.);
#535=CARTESIAN_POINT('',(42.0624,12.8316097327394,0.));
#536=LINE('',#535,#534);
#537=CARTESIAN_POINT('',(42.0624,12.8316097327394,0.));
#538=VERTEX_POINT('',#537);
#539=EDGE_CURVE('E202',#538,#530,#536,.T.);
#540=ORIENTED_EDGE('',*,*,#539,.F.);
#541=DIRECTION('',(0.,0.5,0.866025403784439));
#542=VECTOR('',#541,1.);
#543=CARTESIAN_POINT('',(42.0624,6.41580486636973,-11.1125));
#544=LINE('',#543,#542);
#545=EDGE_CURVE('E184',#507,#538,#544,.T.);
#546=ORIENTED_EDGE('',*,*,#545,.F.);
#547=ORIENTED_EDGE('',*,*,#508,.T.);
#548=EDGE_LOOP('',(#532,#540,#546,#547));
#549=FACE_BOUND('',#548,.T.);
#550=ADVANCED_FACE('F321',(#549),#524,.F.);
#551=CARTESIAN_POINT('',(42.0624,12.8316097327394,0.));
#552=DIRECTION('',(0.,-0.866025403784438,-0.500000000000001));
#553=DIRECTION('',(0.,0.500000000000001,-0.866025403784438));
#554=AXIS2_PLACEMENT_3D('',#551,#552,#553);
#555=PLANE('',#554);
#556=DIRECTION('',(0.,-0.500000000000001,0.866025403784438));
#557=VECTOR('',#556,1.);
#558=CARTESIAN_POINT('',(0.,12.8316097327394,0.));
#559=LINE('',#558,#557);
#560=EDGE_CURVE('E178',#530,#386,#559,.T.);
#561=ORIENTED_EDGE('',*,*,#560,.T.);
#562=ORIENTED_EDGE('',*,*,#411,.F.);
#563=DIRECTION('',(0.,-0.500000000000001,0.866025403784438));
#564=VECTOR('',#563,1.);
#565=CARTESIAN_POINT('',(42.0624,12.8316097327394,0.));
#566=LINE('',#565,#564);
#567=EDGE_CURVE('E186',#538,#404,#566,.T.);
#568=ORIENTED_EDGE('',*,*,#567,.F.);
#569=ORIENTED_EDGE('',*,*,#539,.T.);
#570=EDGE_LOOP('',(#561,#562,#568,#569));
#571=FACE_BOUND('',#570,.T.);
#572=ADVANCED_FACE('F314',(#571),#555,.F.);
#573=CARTESIAN_POINT('',(42.0624,-6.41580486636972,11.1125));
#574=DIRECTION('',(1.,0.,0.));
#575=DIRECTION('',(0.,0.,-1.));
#576=AXIS2_PLACEMENT_3D('',#573,#574,#575);
#577=PLANE('',#576);
#578=CARTESIAN_POINT('',(42.0624,0.,0.));
#579=DIRECTION('',(1.,0.,0.));
#580=DIRECTION('',(0.,0.,-1.));
#581=AXIS2_PLACEMENT_3D('',#578,#579,#580);
#582=CIRCLE('',#581,9.525);
#583=CARTESIAN_POINT('',(42.0624,0.,-9.525));
#584=VERTEX_POINT('',#583);
#585=EDGE_CURVE('E169',#584,#584,#582,.T.);
#586=ORIENTED_EDGE('',*,*,#585,.F.);
#587=EDGE_LOOP('',(#586));
#588=FACE_BOUND('',#587,.T.);
#589=ORIENTED_EDGE('',*,*,#405,.T.);
#590=ORIENTED_EDGE('',*,*,#441,.T.);
#591=ORIENTED_EDGE('',*,*,#472,.T.);
#592=ORIENTED_EDGE('',*,*,#514,.T.);
#593=ORIENTED_EDGE('',*,*,#545,.T.);
#594=ORIENTED_EDGE('',*,*,#567,.T.);
#595=EDGE_LOOP('',(#589,#590,#591,#592,#593,#594));
#596=FACE_BOUND('',#595,.T.);
#597=ADVANCED_FACE('F311',(#588,#596),#577,.T.);
#598=CARTESIAN_POINT('',(0.,-6.41580486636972,11.1125));
#599=DIRECTION('',(1.,0.,0.));
#600=DIRECTION('',(0.,0.,-1.));
#601=AXIS2_PLACEMENT_3D('',#598,#599,#600);
#602=PLANE('',#601);
#603=ORIENTED_EDGE('',*,*,#389,.F.);
#604=ORIENTED_EDGE('',*,*,#560,.F.);
#605=ORIENTED_EDGE('',*,*,#531,.F.);
#606=ORIENTED_EDGE('',*,*,#500,.F.);
#607=ORIENTED_EDGE('',*,*,#458,.F.);
#608=ORIENTED_EDGE('',*,*,#427,.F.);
#609=EDGE_LOOP('',(#603,#604,#605,#606,#607,#608));
#610=FACE_BOUND('',#609,.T.);
#611=ADVANCED_FACE('F309',(#610),#602,.F.);
#612=CARTESIAN_POINT('',(49.1744,0.,0.));
#613=DIRECTION('',(-1.,0.,0.));
#614=DIRECTION('',(0.,0.,1.));
#615=AXIS2_PLACEMENT_3D('',#612,#613,#614);
#616=CYLINDRICAL_SURFACE('',#615,9.525);
#617=ORIENTED_EDGE('',*,*,#585,.T.);
#618=EDGE_LOOP('',(#617));
#619=FACE_BOUND('',#618,.T.);
#620=ORIENTED_EDGE('',*,*,#31,.T.);
#621=EDGE_LOOP('',(#620));
#622=FACE_BOUND('',#621,.T.);
#623=ADVANCED_FACE('F306',(#619,#622),#616,.T.);
#624=CARTESIAN_POINT('',(8.128,0.,11.1125));
#625=DIRECTION('',(0.,0.,1.));
#626=DIRECTION('',(1.,0.,0.));
#627=AXIS2_PLACEMENT_3D('',#624,#625,#626);
#628=CYLINDRICAL_SURFACE('',#627,4.2164);
#629=CARTESIAN_POINT('',(11.52906,-2.49215164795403,-1.05202004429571));
#630=CARTESIAN_POINT('',(11.551953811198,-2.46091333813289,-1.12600198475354));
#631=CARTESIAN_POINT('',(11.57644076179,-2.42658964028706,-1.19813612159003));
#632=CARTESIAN_POINT('',(11.6276567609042,-2.3521190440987,-1.33843781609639));
#633=CARTESIAN_POINT('',(11.654384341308,-2.31197594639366,-1.4066079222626));
#634=CARTESIAN_POINT('',(11.7092439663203,-2.22605619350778,-1.53898681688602));
#635=CARTESIAN_POINT('',(11.7373796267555,-2.18026454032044,-1.60318434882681));
#636=CARTESIAN_POINT('',(11.7941517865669,-2.08339099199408,-1.72720685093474));
#637=CARTESIAN_POINT('',(11.8227883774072,-2.03230812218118,-1.78703101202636));
#638=CARTESIAN_POINT('',(11.9081804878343,-1.871610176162,-1.9594097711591));
#639=CARTESIAN_POINT('',(11.9645593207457,-1.75433496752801,-2.06519436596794));
#640=CARTESIAN_POINT('',(12.0704316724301,-1.50133931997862,-2.25578343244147));
#641=CARTESIAN_POINT('',(12.1199361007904,-1.36564879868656,-2.34062131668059));
#642=CARTESIAN_POINT('',(12.1993785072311,-1.10330875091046,-2.4734517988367));
#643=CARTESIAN_POINT('',(12.2312219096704,-0.979188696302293,-2.52528585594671));
#644=CARTESIAN_POINT('',(12.2840927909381,-0.722527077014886,-2.61031805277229));
#645=CARTESIAN_POINT('',(12.3051273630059,-0.589991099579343,-2.64352841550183));
#646=CARTESIAN_POINT('',(12.3344898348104,-0.31944757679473,-2.68968689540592));
#647=CARTESIAN_POINT('',(12.3427655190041,-0.181419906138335,-2.7025517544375));
#648=CARTESIAN_POINT('',(12.3455928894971,0.0951209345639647,-2.70695991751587));
#649=CARTESIAN_POINT('',(12.3401457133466,0.233634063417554,-2.69850498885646));
#650=CARTESIAN_POINT('',(12.316938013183,0.497113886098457,-2.66212542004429));
#651=CARTESIAN_POINT('',(12.300054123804,0.622355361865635,-2.63558614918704));
#652=CARTESIAN_POINT('',(12.2563243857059,0.866211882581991,-2.56580131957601));
#653=CARTESIAN_POINT('',(12.2294780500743,0.984826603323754,-2.52255494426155));
#654=CARTESIAN_POINT('',(12.1660571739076,1.21974354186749,-2.41811176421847));
#655=CARTESIAN_POINT('',(12.1290114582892,1.33551926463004,-2.35602469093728));
#656=CARTESIAN_POINT('',(12.0487416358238,1.55549159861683,-2.21697435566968));
#657=CARTESIAN_POINT('',(12.0055107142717,1.65967520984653,-2.13999465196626));
#658=CARTESIAN_POINT('',(11.9090617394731,1.87000531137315,-1.96024925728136));
#659=CARTESIAN_POINT('',(11.8553202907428,1.97408280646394,-1.85534597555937));
#660=CARTESIAN_POINT('',(11.7484312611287,2.16387116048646,-1.6299949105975));
#661=CARTESIAN_POINT('',(11.6952829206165,2.2496089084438,-1.50957030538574));
#662=CARTESIAN_POINT('',(11.6245031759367,2.35667455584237,-1.32943935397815));
#663=CARTESIAN_POINT('',(11.6043208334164,2.38628972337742,-1.27553864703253));
#664=CARTESIAN_POINT('',(11.5654609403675,2.44193328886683,-1.16547069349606));
#665=CARTESIAN_POINT('',(11.5467819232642,2.46796520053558,-1.10930573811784));
#666=CARTESIAN_POINT('',(11.52906,2.49215164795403,-1.05202004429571));
#667=B_SPLINE_CURVE_WITH_KNOTS('',3,(#629,#630,#631,#632,#633,#634,#635,#636,#637,#638,#639,
#640,#641,#642,#643,#644,#645,#646,#647,#648,#649,#650,#651,#652,#653,#654,#655,#656,#657,#658,
#659,#660,#661,#662,#663,#664,#665,#666),.UNSPECIFIED.,.F.,.F.,(4,2,2,2,2,2,2,2,2,2,2,2,2,2,2,2,
2,2,4),(0.,0.250358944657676,0.500555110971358,0.751430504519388,1.0023521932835,
1.50297642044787,2.00279685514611,2.4157213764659,2.82837457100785,3.24271210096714,
3.65701528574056,4.042697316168,4.42839819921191,4.83630965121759,5.24467404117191,
5.71456146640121,6.18375516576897,6.37780771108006,6.57166859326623),.UNSPECIFIED.);
#668=CARTESIAN_POINT('',(11.52906,-2.49215164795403,-1.05202004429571));
#669=VERTEX_POINT('',#668);
#670=CARTESIAN_POINT('',(11.52906,2.49215164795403,-1.05202004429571));
#671=VERTEX_POINT('',#670);
#672=EDGE_CURVE('E250',#669,#671,#667,.T.);
#673=ORIENTED_EDGE('',*,*,#672,.T.);
#674=CARTESIAN_POINT('',(12.1820137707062,1.1588793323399,-3.61036389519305));
#675=CARTESIAN_POINT('',(12.1632135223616,1.22458333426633,-3.55639498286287));
#676=CARTESIAN_POINT('',(12.1435607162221,1.2873514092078,-3.49931750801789));
#677=CARTESIAN_POINT('',(12.1031293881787,1.40727052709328,-3.38008501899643));
#678=CARTESIAN_POINT('',(12.0823528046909,1.46443079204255,-3.31793865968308));
#679=CARTESIAN_POINT('',(12.0403145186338,1.57327579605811,-3.18990951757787));
#680=CARTESIAN_POINT('',(12.0190565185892,1.62499161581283,-3.1240516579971));
#681=CARTESIAN_POINT('',(11.9763463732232,1.72370346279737,-2.98893000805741));
#682=CARTESIAN_POINT('',(11.9548941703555,1.77069803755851,-2.91966517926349));
#683=CARTESIAN_POINT('',(11.9085779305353,1.86778428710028,-2.76639473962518));
#684=CARTESIAN_POINT('',(11.8837467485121,1.91706797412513,-2.68186890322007));
#685=CARTESIAN_POINT('',(11.8297019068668,2.01977065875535,-2.49139948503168));
#686=CARTESIAN_POINT('',(11.8006672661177,2.07187293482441,-2.38469575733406));
#687=CARTESIAN_POINT('',(11.7445507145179,2.16834133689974,-2.16720179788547));
#688=CARTESIAN_POINT('',(11.7174713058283,2.21269764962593,-2.05640659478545));
#689=CARTESIAN_POINT('',(11.6632981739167,2.29837805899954,-1.81906548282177));
#690=CARTESIAN_POINT('',(11.6365315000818,2.3388298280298,-1.69212901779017));
#691=CARTESIAN_POINT('',(11.587563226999,2.4106724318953,-1.43480166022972));
#692=CARTESIAN_POINT('',(11.5653633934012,2.44205976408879,-1.30440945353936));
#693=CARTESIAN_POINT('',(11.5265712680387,2.49576497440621,-1.04085346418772));
#694=CARTESIAN_POINT('',(11.509982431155,2.51807726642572,-0.907688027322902));
#695=CARTESIAN_POINT('',(11.4833210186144,2.55349626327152,-0.639507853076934));
#696=CARTESIAN_POINT('',(11.4732473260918,2.56660454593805,-0.504493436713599));
#697=CARTESIAN_POINT('',(11.4599592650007,2.58383509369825,-0.228322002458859));
#698=CARTESIAN_POINT('',(11.457023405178,2.58759263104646,-0.0871283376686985));
#699=CARTESIAN_POINT('',(11.459018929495,2.5850229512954,0.195134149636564));
#700=CARTESIAN_POINT('',(11.4639516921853,2.57869396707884,0.336202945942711));
#701=CARTESIAN_POINT('',(11.4813482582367,2.55602920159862,0.616925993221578));
#702=CARTESIAN_POINT('',(11.4938052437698,2.5397024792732,0.756581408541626));
#703=CARTESIAN_POINT('',(11.5254656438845,2.49718969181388,1.0335471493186));
#704=CARTESIAN_POINT('',(11.5446664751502,2.47100740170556,1.17085835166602));
#705=CARTESIAN_POINT('',(11.5843401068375,2.41509098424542,1.41515743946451));
#706=CARTESIAN_POINT('',(11.6037915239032,2.38711288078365,1.52272040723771));
#707=CARTESIAN_POINT('',(11.6456996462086,2.32491397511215,1.7353082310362));
#708=CARTESIAN_POINT('',(11.6681530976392,2.2906999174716,1.84033569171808));
#709=CARTESIAN_POINT('',(11.710375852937,2.22391951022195,2.02532027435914));
#710=CARTESIAN_POINT('',(11.7296887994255,2.19257208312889,2.10582546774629));
#711=CARTESIAN_POINT('',(11.7741465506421,2.11800599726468,2.28351481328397));
#712=CARTESIAN_POINT('',(11.7995967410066,2.07372747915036,2.38018212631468));
#713=CARTESIAN_POINT('',(11.8516649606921,1.97870638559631,2.56996053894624));
#714=CARTESIAN_POINT('',(11.8782829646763,1.92796395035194,2.66307171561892));
#715=CARTESIAN_POINT('',(11.9322040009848,1.81928075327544,2.84556246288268));
#716=CARTESIAN_POINT('',(11.9595099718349,1.76130233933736,2.9349189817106));
#717=CARTESIAN_POINT('',(12.0139375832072,1.63768558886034,3.10835391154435));
#718=CARTESIAN_POINT('',(12.0410590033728,1.57203937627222,3.19242675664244));
#719=CARTESIAN_POINT('',(12.0676941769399,1.50227785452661,3.27326073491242));
#720=B_SPLINE_CURVE_WITH_KNOTS('',3,(#674,#675,#676,#677,#678,#679,#680,#681,#682,#683,#684,
#685,#686,#687,#688,#689,#690,#691,#692,#693,#694,#695,#696,#697,#698,#699,#700,#701,#702,#703,
#704,#705,#706,#707,#708,#709,#710,#711,#712,#713,#714,#715,#716,#717,#718,#719),.UNSPECIFIED.,
.F.,.F.,(4,2,2,2,2,2,2,2,2,2,2,2,2,2,2,2,2,2,2,2,2,2,4),(0.,0.260983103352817,0.521529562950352,
0.780497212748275,1.03954429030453,1.34215055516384,1.70851791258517,2.07534610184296,
2.48258479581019,2.88998064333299,3.29762688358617,3.7052032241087,4.12844418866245,
4.55175931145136,4.97469143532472,5.39746172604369,5.73572726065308,6.07362908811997,
6.33909874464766,6.66683431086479,6.99456277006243,7.32407381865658,7.65392635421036),.UNSPECIFIED.);
#721=CARTESIAN_POINT('',(11.52906,2.49215164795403,1.05202004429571));
#722=VERTEX_POINT('',#721);
#723=EDGE_CURVE('E137',#671,#722,#720,.T.);
#724=ORIENTED_EDGE('',*,*,#723,.T.);
#725=CARTESIAN_POINT('',(11.52906,2.49215164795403,1.05202004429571));
#726=CARTESIAN_POINT('',(11.551953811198,2.46091333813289,1.12600198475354));
#727=CARTESIAN_POINT('',(11.57644076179,2.42658964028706,1.19813612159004));
#728=CARTESIAN_POINT('',(11.6276567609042,2.3521190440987,1.33843781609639));
#729=CARTESIAN_POINT('',(11.654384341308,2.31197594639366,1.4066079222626));
#730=CARTESIAN_POINT('',(11.7092439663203,2.22605619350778,1.53898681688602));
#731=CARTESIAN_POINT('',(11.7373796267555,2.18026454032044,1.60318434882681));
#732=CARTESIAN_POINT('',(11.7941517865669,2.08339099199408,1.72720685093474));
#733=CARTESIAN_POINT('',(11.8227883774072,2.03230812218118,1.78703101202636));
#734=CARTESIAN_POINT('',(11.9081804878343,1.871610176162,1.9594097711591));
#735=CARTESIAN_POINT('',(11.9645593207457,1.75433496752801,2.06519436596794));
#736=CARTESIAN_POINT('',(12.0704316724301,1.50133931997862,2.25578343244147));
#737=CARTESIAN_POINT('',(12.1199361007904,1.36564879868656,2.34062131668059));
#738=CARTESIAN_POINT('',(12.1993785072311,1.10330875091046,2.4734517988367));
#739=CARTESIAN_POINT('',(12.2312219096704,0.979188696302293,2.52528585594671));
#740=CARTESIAN_POINT('',(12.2840927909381,0.722527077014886,2.6103180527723));
#741=CARTESIAN_POINT('',(12.3051273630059,0.589991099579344,2.64352841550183));
#742=CARTESIAN_POINT('',(12.3344898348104,0.319447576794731,2.68968689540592));
#743=CARTESIAN_POINT('',(12.3427655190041,0.181419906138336,2.7025517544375));
#744=CARTESIAN_POINT('',(12.3455928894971,-0.0951209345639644,2.70695991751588));
#745=CARTESIAN_POINT('',(12.3401457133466,-0.233634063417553,2.69850498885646));
#746=CARTESIAN_POINT('',(12.316938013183,-0.497113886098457,2.66212542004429));
#747=CARTESIAN_POINT('',(12.300054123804,-0.622355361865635,2.63558614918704));
#748=CARTESIAN_POINT('',(12.2563243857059,-0.86621188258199,2.56580131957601));
#749=CARTESIAN_POINT('',(12.2294780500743,-0.984826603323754,2.52255494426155));
#750=CARTESIAN_POINT('',(12.1660571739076,-1.21974354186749,2.41811176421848));
#751=CARTESIAN_POINT('',(12.1290114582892,-1.33551926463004,2.35602469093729));
#752=CARTESIAN_POINT('',(12.0487416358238,-1.55549159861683,2.21697435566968));
#753=CARTESIAN_POINT('',(12.0055107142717,-1.65967520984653,2.13999465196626));
#754=CARTESIAN_POINT('',(11.9090617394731,-1.87000531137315,1.96024925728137));
#755=CARTESIAN_POINT('',(11.8553202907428,-1.97408280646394,1.85534597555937));
#756=CARTESIAN_POINT('',(11.7484312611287,-2.16387116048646,1.62999491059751));
#757=CARTESIAN_POINT('',(11.6952829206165,-2.2496089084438,1.50957030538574));
#758=CARTESIAN_POINT('',(11.6245031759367,-2.35667455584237,1.32943935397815));
#759=CARTESIAN_POINT('',(11.6043208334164,-2.38628972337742,1.27553864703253));
#760=CARTESIAN_POINT('',(11.5654609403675,-2.44193328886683,1.16547069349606));
#761=CARTESIAN_POINT('',(11.5467819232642,-2.46796520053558,1.10930573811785));
#762=CARTESIAN_POINT('',(11.52906,-2.49215164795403,1.05202004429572));
#763=B_SPLINE_CURVE_WITH_KNOTS('',3,(#725,#726,#727,#728,#729,#730,#731,#732,#733,#734,#735,
#736,#737,#738,#739,#740,#741,#742,#743,#744,#745,#746,#747,#748,#749,#750,#751,#752,#753,#754,
#755,#756,#757,#758,#759,#760,#761,#762),.UNSPECIFIED.,.F.,.F.,(4,2,2,2,2,2,2,2,2,2,2,2,2,2,2,2,
2,2,4),(0.,0.250358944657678,0.50055511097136,0.751430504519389,1.0023521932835,
1.50297642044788,2.00279685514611,2.4157213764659,2.82837457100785,3.24271210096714,
3.65701528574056,4.042697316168,4.42839819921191,4.83630965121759,5.24467404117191,
5.71456146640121,6.18375516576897,6.37780771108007,6.57166859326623),.UNSPECIFIED.);
#764=CARTESIAN_POINT('',(11.52906,-2.49215164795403,1.05202004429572));
#765=VERTEX_POINT('',#764);
#766=EDGE_CURVE('E223',#722,#765,#763,.T.);
#767=ORIENTED_EDGE('',*,*,#766,.T.);
#768=CARTESIAN_POINT('',(12.0676941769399,-1.50227785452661,3.27326073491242));
#769=CARTESIAN_POINT('',(12.0397438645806,-1.57547104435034,3.18843482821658));
#770=CARTESIAN_POINT('',(12.0112627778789,-1.64413878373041,3.10005789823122));
#771=CARTESIAN_POINT('',(11.9541372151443,-1.77306291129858,2.91753716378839));
#772=CARTESIAN_POINT('',(11.9254929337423,-1.83332774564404,2.82339928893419));
#773=CARTESIAN_POINT('',(11.8691348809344,-1.94572072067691,2.63138673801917));
#774=CARTESIAN_POINT('',(11.8414150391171,-1.99791748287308,2.53355352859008));
#775=CARTESIAN_POINT('',(11.78735076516,-2.09530133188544,2.33410167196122));
#776=CARTESIAN_POINT('',(11.7610061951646,-2.14048912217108,2.23248340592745));
#777=CARTESIAN_POINT('',(11.7206770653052,-2.20715607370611,2.06804319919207));
#778=CARTESIAN_POINT('',(11.7060227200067,-2.23080395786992,2.00624858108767));
#779=CARTESIAN_POINT('',(11.6633214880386,-2.29834281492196,1.81916750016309));
#780=CARTESIAN_POINT('',(11.6365694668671,-2.33877280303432,1.69230867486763));
#781=CARTESIAN_POINT('',(11.5876219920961,-2.41058753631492,1.43513029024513));
#782=CARTESIAN_POINT('',(11.5654291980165,-2.44196700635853,1.30480876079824));
#783=CARTESIAN_POINT('',(11.5266219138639,-2.49569651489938,1.04124519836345));
#784=CARTESIAN_POINT('',(11.5100171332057,-2.51803085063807,0.907998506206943));
#785=CARTESIAN_POINT('',(11.4833324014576,-2.55348145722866,0.639660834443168));
#786=CARTESIAN_POINT('',(11.4732510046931,-2.56659977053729,0.504570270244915));
#787=CARTESIAN_POINT('',(11.45995522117,-2.5838403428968,0.228237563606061));
#788=CARTESIAN_POINT('',(11.4570199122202,-2.58759713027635,0.0869586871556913));
#789=CARTESIAN_POINT('',(11.4590260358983,-2.58501379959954,-0.1954741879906));
#790=CARTESIAN_POINT('',(11.4639689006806,-2.578671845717,-0.336628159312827));
#791=CARTESIAN_POINT('',(11.4813835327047,-2.55598295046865,-0.617347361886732));
#792=CARTESIAN_POINT('',(11.4938392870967,-2.53965728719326,-0.75691533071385));
#793=CARTESIAN_POINT('',(11.5254884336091,-2.49715857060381,-1.0337103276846));
#794=CARTESIAN_POINT('',(11.5446793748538,-2.47098909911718,-1.17093818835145));
#795=CARTESIAN_POINT('',(11.5843138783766,-2.4151280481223,-1.41499560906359));
#796=CARTESIAN_POINT('',(11.6037338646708,-2.38719615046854,-1.52240083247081));
#797=CARTESIAN_POINT('',(11.6456317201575,-2.32501709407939,-1.73499067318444));
#798=CARTESIAN_POINT('',(11.6681153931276,-2.29075790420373,-1.84017062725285));
#799=CARTESIAN_POINT('',(11.7204658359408,-2.20796297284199,-2.06952593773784));
#800=CARTESIAN_POINT('',(11.7508906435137,-2.15794003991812,-2.19304113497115));
#801=CARTESIAN_POINT('',(11.8141287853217,-2.04804983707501,-2.43512726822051));
#802=CARTESIAN_POINT('',(11.8469440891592,-1.98817439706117,-2.5536939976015));
#803=CARTESIAN_POINT('',(11.9135875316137,-1.85813825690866,-2.78408395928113));
#804=CARTESIAN_POINT('',(11.9474108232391,-1.78802193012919,-2.89593348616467));
#805=CARTESIAN_POINT('',(12.0148176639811,-1.63632594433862,-3.11152308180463));
#806=CARTESIAN_POINT('',(12.0484015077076,-1.55476459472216,-3.21527569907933));
#807=CARTESIAN_POINT('',(12.0986300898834,-1.41939340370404,-3.36661569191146));
#808=CARTESIAN_POINT('',(12.1159472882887,-1.37012089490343,-3.41804789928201));
#809=CARTESIAN_POINT('',(12.1497190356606,-1.26756012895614,-3.517186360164));
#810=CARTESIAN_POINT('',(12.166172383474,-1.21426651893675,-3.56488746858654));
#811=CARTESIAN_POINT('',(12.1820137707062,-1.1588793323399,-3.61036389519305));
#812=B_SPLINE_CURVE_WITH_KNOTS('',3,(#768,#769,#770,#771,#772,#773,#774,#775,#776,#777,#778,
#779,#780,#781,#782,#783,#784,#785,#786,#787,#788,#789,#790,#791,#792,#793,#794,#795,#796,#797,
#798,#799,#800,#801,#802,#803,#804,#805,#806,#807,#808,#809,#810,#811),.UNSPECIFIED.,.F.,.F.,(4,
2,2,2,2,2,2,2,2,2,2,2,2,2,2,2,2,2,2,2,2,4),(0.,0.346084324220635,0.691818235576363,
1.03442716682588,1.37700168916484,1.5802696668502,1.98722705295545,2.39442115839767,
2.80231917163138,3.21012675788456,3.63362185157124,4.0571939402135,4.47986640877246,
4.90238522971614,5.24014442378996,5.57855259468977,5.98817080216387,6.39813040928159,
6.8063636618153,7.21395112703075,7.43366415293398,7.65367500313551),.UNSPECIFIED.);
#813=EDGE_CURVE('E172',#765,#669,#812,.T.);
#814=ORIENTED_EDGE('',*,*,#813,.T.);
#815=EDGE_LOOP('',(#673,#724,#767,#814));
#816=FACE_BOUND('',#815,.T.);
#817=CARTESIAN_POINT('',(8.128,0.,-4.18846));
#818=DIRECTION('',(0.,0.,-1.));
#819=DIRECTION('',(-1.,0.,0.));
#820=AXIS2_PLACEMENT_3D('',#817,#818,#819);
#821=CIRCLE('',#820,4.21640000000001);
#822=CARTESIAN_POINT('',(3.91159999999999,0.,-4.18846));
#823=VERTEX_POINT('',#822);
#824=EDGE_CURVE('E594',#823,#823,#821,.T.);
#825=ORIENTED_EDGE('',*,*,#824,.T.);
#826=EDGE_LOOP('',(#825));
#827=FACE_BOUND('',#826,.T.);
#828=CARTESIAN_POINT('',(8.128,0.,4.18846));
#829=DIRECTION('',(0.,0.,1.));
#830=DIRECTION('',(1.,0.,0.));
#831=AXIS2_PLACEMENT_3D('',#828,#829,#830);
#832=CIRCLE('',#831,4.2164);
#833=CARTESIAN_POINT('',(12.3444,0.,4.18846));
#834=VERTEX_POINT('',#833);
#835=EDGE_CURVE('E155',#834,#834,#832,.T.);
#836=ORIENTED_EDGE('',*,*,#835,.T.);
#837=EDGE_LOOP('',(#836));
#838=FACE_BOUND('',#837,.T.);
#839=ADVANCED_FACE('F229',(#816,#827,#838),#628,.F.);
#840=CARTESIAN_POINT('',(12.3444,0.,4.18846));
#841=DIRECTION('',(0.,0.,-1.));
#842=DIRECTION('',(-1.,0.,0.));
#843=AXIS2_PLACEMENT_3D('',#840,#841,#842);
#844=PLANE('',#843);
#845=ORIENTED_EDGE('',*,*,#835,.F.);
#846=EDGE_LOOP('',(#845));
#847=FACE_BOUND('',#846,.T.);
#848=CARTESIAN_POINT('',(8.128,0.,4.18846));
#849=DIRECTION('',(0.,0.,1.));
#850=DIRECTION('',(1.,0.,0.));
#851=AXIS2_PLACEMENT_3D('',#848,#849,#850);
#852=CIRCLE('',#851,4.93618496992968);
#853=CARTESIAN_POINT('',(13.0641849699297,0.,4.18846));
#854=VERTEX_POINT('',#853);
#855=EDGE_CURVE('E598',#854,#854,#852,.T.);
#856=ORIENTED_EDGE('',*,*,#855,.T.);
#857=EDGE_LOOP('',(#856));
#858=FACE_BOUND('',#857,.T.);
#859=ADVANCED_FACE('F452',(#847,#858),#844,.F.);
#860=CARTESIAN_POINT('',(8.128,0.,11.1125));
#861=DIRECTION('',(0.,0.,1.));
#862=DIRECTION('',(1.,0.,0.));
#863=AXIS2_PLACEMENT_3D('',#860,#861,#862);
#864=CONICAL_SURFACE('',#863,5.1435,0.0299323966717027);
#865=ORIENTED_EDGE('',*,*,#855,.F.);
#866=EDGE_LOOP('',(#865));
#867=FACE_BOUND('',#866,.T.);
#868=ORIENTED_EDGE('',*,*,#374,.T.);
#869=EDGE_LOOP('',(#868));
#870=FACE_BOUND('',#869,.T.);
#871=ADVANCED_FACE('F457',(#867,#870),#864,.F.);
#872=CARTESIAN_POINT('',(12.3444,0.,-4.18846));
#873=DIRECTION('',(0.,0.,1.));
#874=DIRECTION('',(1.,0.,0.));
#875=AXIS2_PLACEMENT_3D('',#872,#873,#874);
#876=PLANE('',#875);
#877=ORIENTED_EDGE('',*,*,#824,.F.);
#878=EDGE_LOOP('',(#877));
#879=FACE_BOUND('',#878,.T.);
#880=CARTESIAN_POINT('',(8.128,0.,-4.18846));
#881=DIRECTION('',(0.,0.,-1.));
#882=DIRECTION('',(-1.,0.,0.));
#883=AXIS2_PLACEMENT_3D('',#880,#881,#882);
#884=CIRCLE('',#883,4.93618496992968);
#885=CARTESIAN_POINT('',(3.19181503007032,0.,-4.18846));
#886=VERTEX_POINT('',#885);
#887=EDGE_CURVE('E588',#886,#886,#884,.T.);
#888=ORIENTED_EDGE('',*,*,#887,.T.);
#889=EDGE_LOOP('',(#888));
#890=FACE_BOUND('',#889,.T.);
#891=ADVANCED_FACE('F467',(#879,#890),#876,.F.);
#892=CARTESIAN_POINT('',(8.128,0.,-11.1125));
#893=DIRECTION('',(0.,0.,-1.));
#894=DIRECTION('',(-1.,0.,0.));
#895=AXIS2_PLACEMENT_3D('',#892,#893,#894);
#896=CONICAL_SURFACE('',#895,5.1435,0.0299323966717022);
#897=ORIENTED_EDGE('',*,*,#887,.F.);
#898=EDGE_LOOP('',(#897));
#899=FACE_BOUND('',#898,.T.);
#900=ORIENTED_EDGE('',*,*,#490,.T.);
#901=EDGE_LOOP('',(#900));
#902=FACE_BOUND('',#901,.T.);
#903=ADVANCED_FACE('F241',(#899,#902),#896,.F.);
#904=CARTESIAN_POINT('',(19.2024,2.70509999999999,0.));
#905=DIRECTION('',(-1.,0.,0.));
#906=DIRECTION('',(0.,0.,1.));
#907=AXIS2_PLACEMENT_3D('',#904,#905,#906);
#908=PLANE('',#907);
#909=CARTESIAN_POINT('',(19.2024,0.,0.));
#910=DIRECTION('',(1.,0.,0.));
#911=DIRECTION('',(0.,0.,-1.));
#912=AXIS2_PLACEMENT_3D('',#909,#910,#911);
#913=CIRCLE('',#912,2.70509999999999);
#914=CARTESIAN_POINT('',(19.2024,0.,-2.70509999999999));
#915=VERTEX_POINT('',#914);
#916=EDGE_CURVE('E578',#915,#915,#913,.T.);
#917=ORIENTED_EDGE('',*,*,#916,.F.);
#918=EDGE_LOOP('',(#917));
#919=FACE_BOUND('',#918,.T.);
#920=ORIENTED_EDGE('',*,*,#346,.T.);
#921=EDGE_LOOP('',(#920));
#922=FACE_BOUND('',#921,.T.);
#923=ADVANCED_FACE('F493',(#919,#922),#908,.F.);
#924=CARTESIAN_POINT('',(11.52906,0.,0.));
#925=DIRECTION('',(1.,0.,0.));
#926=DIRECTION('',(0.,0.,-1.));
#927=AXIS2_PLACEMENT_3D('',#924,#925,#926);
#928=CONICAL_SURFACE('',#927,2.70509999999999,1.02974425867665);
#929=CARTESIAN_POINT('',(11.52906,0.,0.));
#930=DIRECTION('',(1.,0.,0.));
#931=DIRECTION('',(0.,0.,-1.));
#932=AXIS2_PLACEMENT_3D('',#929,#930,#931);
#933=CIRCLE('',#932,2.70509999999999);
#934=EDGE_CURVE('E62',#765,#669,#933,.T.);
#935=ORIENTED_EDGE('',*,*,#934,.T.);
#936=ORIENTED_EDGE('',*,*,#813,.F.);
#937=EDGE_LOOP('',(#935,#936));
#938=FACE_BOUND('',#937,.T.);
#939=ADVANCED_FACE('F237',(#938),#928,.F.);
#940=EDGE_CURVE('E583',#671,#722,#933,.T.);
#941=ORIENTED_EDGE('',*,*,#940,.T.);
#942=ORIENTED_EDGE('',*,*,#723,.F.);
#943=EDGE_LOOP('',(#941,#942));
#944=FACE_BOUND('',#943,.T.);
#945=ADVANCED_FACE('F232',(#944),#928,.F.);
#946=CARTESIAN_POINT('',(49.1744,0.,0.));
#947=DIRECTION('',(1.,0.,0.));
#948=DIRECTION('',(0.,0.,-1.));
#949=AXIS2_PLACEMENT_3D('',#946,#947,#948);
#950=CYLINDRICAL_SURFACE('',#949,2.70509999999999);
#951=ORIENTED_EDGE('',*,*,#916,.T.);
#952=EDGE_LOOP('',(#951));
#953=FACE_BOUND('',#952,.T.);
#954=ORIENTED_EDGE('',*,*,#934,.F.);
#955=ORIENTED_EDGE('',*,*,#766,.F.);
#956=ORIENTED_EDGE('',*,*,#940,.F.);
#957=ORIENTED_EDGE('',*,*,#672,.F.);
#958=EDGE_LOOP('',(#954,#955,#956,#957));
#959=FACE_BOUND('',#958,.T.);
#960=ADVANCED_FACE('F236',(#953,#959),#950,.F.);
#961=CARTESIAN_POINT('',(0.,0.,0.));
#962=DIRECTION('',(-1.,0.,0.));
#963=DIRECTION('',(0.,0.,1.));
#964=AXIS2_PLACEMENT_3D('',#961,#962,#963);
#965=CYLINDRICAL_SURFACE('',#964,4.3688);
#966=CARTESIAN_POINT('',(42.2402,0.,0.));
#967=DIRECTION('',(-1.,0.,0.));
#968=DIRECTION('',(0.,0.,1.));
#969=AXIS2_PLACEMENT_3D('',#966,#967,#968);
#970=CIRCLE('',#969,4.3688);
#971=CARTESIAN_POINT('',(42.2402,0.,4.3688));
#972=VERTEX_POINT('',#971);
#973=EDGE_CURVE('E390',#972,#972,#970,.T.);
#974=ORIENTED_EDGE('',*,*,#973,.F.);
#975=EDGE_LOOP('',(#974));
#976=FACE_BOUND('',#975,.T.);
#977=CARTESIAN_POINT('',(26.9494,0.,0.));
#978=DIRECTION('',(-1.,0.,0.));
#979=DIRECTION('',(0.,0.,1.));
#980=AXIS2_PLACEMENT_3D('',#977,#978,#979);
#981=CIRCLE('',#980,4.3688);
#982=CARTESIAN_POINT('',(26.9494,0.,4.3688));
#983=VERTEX_POINT('',#982);
#984=EDGE_CURVE('E387',#983,#983,#981,.T.);
#985=ORIENTED_EDGE('',*,*,#984,.T.);
#986=EDGE_LOOP('',(#985));
#987=FACE_BOUND('',#986,.T.);
#988=ORIENTED_EDGE('',*,*,#302,.T.);
#989=ORIENTED_EDGE('',*,*,#251,.T.);
#990=ORIENTED_EDGE('',*,*,#125,.T.);
#991=ORIENTED_EDGE('',*,*,#257,.T.);
#992=ORIENTED_EDGE('',*,*,#328,.T.);
#993=ORIENTED_EDGE('',*,*,#228,.T.);
#994=ORIENTED_EDGE('',*,*,#210,.T.);
#995=ORIENTED_EDGE('',*,*,#239,.T.);
#996=EDGE_LOOP('',(#988,#989,#990,#991,#992,#993,#994,#995));
#997=FACE_BOUND('',#996,.T.);
#998=CARTESIAN_POINT('',(37.7444,0.,-4.3688));
#999=CARTESIAN_POINT('',(37.7443994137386,-0.0952612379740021,-4.36879941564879));
#1000=CARTESIAN_POINT('',(37.7411650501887,-0.190531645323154,-4.36567764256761));
#1001=CARTESIAN_POINT('',(37.7282943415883,-0.380272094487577,-4.35325789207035));
#1002=CARTESIAN_POINT('',(37.7186547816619,-0.474741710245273,-4.34395681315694));
#1003=CARTESIAN_POINT('',(37.6931507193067,-0.6621972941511,-4.31935799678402));
#1004=CARTESIAN_POINT('',(37.6772765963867,-0.755180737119,-4.30405099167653));
#1005=CARTESIAN_POINT('',(37.6396217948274,-0.938830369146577,-4.26776212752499));
#1006=CARTESIAN_POINT('',(37.617838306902,-1.02949543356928,-4.24677756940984));
#1007=CARTESIAN_POINT('',(37.5445553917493,-1.2957356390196,-4.17623316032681));
#1008=CARTESIAN_POINT('',(37.4849025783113,-1.46711011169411,-4.11886891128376));
#1009=CARTESIAN_POINT('',(37.3474150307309,-1.7949445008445,-3.98697179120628));
#1010=CARTESIAN_POINT('',(37.269579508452,-1.95140377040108,-3.91243817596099));
#1011=CARTESIAN_POINT('',(37.0641544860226,-2.30906169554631,-3.71637735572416));
#1012=CARTESIAN_POINT('',(36.9292336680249,-2.50240013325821,-3.58809547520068));
#1013=CARTESIAN_POINT('',(36.7106806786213,-2.76800022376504,-3.38190238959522));
#1014=CARTESIAN_POINT('',(36.6349816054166,-2.8525974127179,-3.31073399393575));
#1015=CARTESIAN_POINT('',(36.4788277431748,-3.01383776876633,-3.16464954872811));
#1016=CARTESIAN_POINT('',(36.3983732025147,-3.09048135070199,-3.08973369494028));
#1017=CARTESIAN_POINT('',(36.2048052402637,-3.26108386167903,-2.91064991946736));
#1018=CARTESIAN_POINT('',(36.0900022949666,-3.35189145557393,-2.80530855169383));
#1019=CARTESIAN_POINT('',(35.8536916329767,-3.51997611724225,-2.59127275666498));
#1020=CARTESIAN_POINT('',(35.7321795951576,-3.59724432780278,-2.48257618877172));
#1021=CARTESIAN_POINT('',(35.4829438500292,-3.73854520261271,-2.26419595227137));
#1022=CARTESIAN_POINT('',(35.3552297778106,-3.80259763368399,-2.15451401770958));
#1023=CARTESIAN_POINT('',(35.0928531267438,-3.91788740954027,-1.93691172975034));
#1024=CARTESIAN_POINT('',(34.9581973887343,-3.96913709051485,-1.82898977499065));
#1025=CARTESIAN_POINT('',(34.725708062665,-4.04389130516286,-1.65503370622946));
#1026=CARTESIAN_POINT('',(34.6305135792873,-4.07095567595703,-1.58700074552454));
#1027=CARTESIAN_POINT('',(34.4342148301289,-4.11910696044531,-1.45742495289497));
#1028=CARTESIAN_POINT('',(34.3331136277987,-4.1401969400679,-1.39587880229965));
#1029=CARTESIAN_POINT('',(34.1554266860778,-4.17010165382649,-1.30317535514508));
#1030=CARTESIAN_POINT('',(34.0810121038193,-4.1806937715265,-1.26852340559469));
#1031=CARTESIAN_POINT('',(33.9277526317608,-4.19811016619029,-1.20964089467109));
#1032=CARTESIAN_POINT('',(33.8489222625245,-4.20494607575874,-1.18537821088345));
#1033=CARTESIAN_POINT('',(33.7047037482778,-4.21317606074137,-1.1557497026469));
#1034=CARTESIAN_POINT('',(33.6399878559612,-4.21541388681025,-1.1474772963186));
#1035=CARTESIAN_POINT('',(33.5101247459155,-4.21686093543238,-1.14215041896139));
#1036=CARTESIAN_POINT('',(33.4449782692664,-4.2160744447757,-1.1450800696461));
#1037=CARTESIAN_POINT('',(33.3023793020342,-4.2110869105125,-1.16329729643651));
#1038=CARTESIAN_POINT('',(33.2252867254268,-4.20618920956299,-1.18110237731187));
#1039=CARTESIAN_POINT('',(33.0748906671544,-4.19267074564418,-1.22821392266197));
#1040=CARTESIAN_POINT('',(33.0016080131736,-4.18403152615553,-1.25757733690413));
#1041=CARTESIAN_POINT('',(32.8370498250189,-4.16046913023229,-1.33376743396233));
#1042=CARTESIAN_POINT('',(32.7471764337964,-4.14443032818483,-1.38318745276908));
#1043=CARTESIAN_POINT('',(32.5724515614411,-4.10766807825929,-1.48883722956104));
#1044=CARTESIAN_POINT('',(32.4876117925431,-4.08693420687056,-1.54508200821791));
#1045=CARTESIAN_POINT('',(32.3212937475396,-4.04096112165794,-1.66162525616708));
#1046=CARTESIAN_POINT('',(32.2398379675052,-4.01569633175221,-1.72194545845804));
#1047=CARTESIAN_POINT('',(32.0800509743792,-3.96088264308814,-1.84454323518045));
#1048=CARTESIAN_POINT('',(32.001717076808,-3.93133753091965,-1.90681904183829));
#1049=CARTESIAN_POINT('',(31.7883652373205,-3.84362384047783,-2.08047481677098));
#1050=CARTESIAN_POINT('',(31.6560013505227,-3.78089469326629,-2.19284658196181));
#1051=CARTESIAN_POINT('',(31.397918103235,-3.64173739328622,-2.4169459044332));
#1052=CARTESIAN_POINT('',(31.2722041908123,-3.56529822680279,-2.52867286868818));
#1053=CARTESIAN_POINT('',(31.0281189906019,-3.39858389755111,-2.74863703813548));
#1054=CARTESIAN_POINT('',(30.9097204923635,-3.30836496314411,-2.8568863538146));
#1055=CARTESIAN_POINT('',(30.6806688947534,-3.11341177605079,-3.06818219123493));
#1056=CARTESIAN_POINT('',(30.570010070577,-3.00868842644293,-3.17123254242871));
#1057=CARTESIAN_POINT('',(30.3267496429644,-2.75133802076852,-3.3991295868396));
#1058=CARTESIAN_POINT('',(30.1971537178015,-2.59364532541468,-3.52157433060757));
#1059=CARTESIAN_POINT('',(29.9577084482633,-2.25263289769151,-3.74886178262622));
#1060=CARTESIAN_POINT('',(29.8478365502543,-2.06934286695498,-3.85372458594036));
#1061=CARTESIAN_POINT('',(29.6716951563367,-1.71422874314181,-4.02230639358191));
#1062=CARTESIAN_POINT('',(29.6011223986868,-1.54650468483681,-4.09004581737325));
#1063=CARTESIAN_POINT('',(29.5110064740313,-1.28465785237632,-4.17666784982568));
#1064=CARTESIAN_POINT('',(29.4835867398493,-1.19564154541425,-4.20304880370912));
#1065=CARTESIAN_POINT('',(29.4344347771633,-1.01465754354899,-4.25036658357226));
#1066=CARTESIAN_POINT('',(29.4127000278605,-0.922691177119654,-4.27130582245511));
#1067=CARTESIAN_POINT('',(29.3751779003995,-0.735703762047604,-4.30746917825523));
#1068=CARTESIAN_POINT('',(29.3594361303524,-0.640665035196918,-4.32264946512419));
#1069=CARTESIAN_POINT('',(29.3344607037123,-0.448989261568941,-4.34673962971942));
#1070=CARTESIAN_POINT('',(29.3252240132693,-0.352352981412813,-4.35565243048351));
#1071=CARTESIAN_POINT('',(29.3134519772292,-0.158305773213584,-4.36701238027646));
#1072=CARTESIAN_POINT('',(29.3109157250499,-0.0608949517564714,-4.36946040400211));
#1073=CARTESIAN_POINT('',(29.312599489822,0.133807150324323,-4.36783537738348));
#1074=CARTESIAN_POINT('',(29.3168189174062,0.231098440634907,-4.36376289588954));
#1075=CARTESIAN_POINT('',(29.3310691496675,0.413795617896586,-4.35001264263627));
#1076=CARTESIAN_POINT('',(29.3403940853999,0.499309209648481,-4.34101574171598));
#1077=CARTESIAN_POINT('',(29.3641253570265,0.668975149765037,-4.31812771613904));
#1078=CARTESIAN_POINT('',(29.3785333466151,0.753127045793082,-4.30423499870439));
#1079=CARTESIAN_POINT('',(29.4290497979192,1.00267901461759,-4.25554865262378));
#1080=CARTESIAN_POINT('',(29.4724626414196,1.16532121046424,-4.21373531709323));
#1081=CARTESIAN_POINT('',(29.5784884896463,1.48635070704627,-4.11178838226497));
#1082=CARTESIAN_POINT('',(29.64184051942,1.64426173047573,-4.05095033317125));
#1083=CARTESIAN_POINT('',(29.7839194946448,1.94621924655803,-3.91485785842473));
#1084=CARTESIAN_POINT('',(29.8626516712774,2.09026099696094,-3.83959852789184));
#1085=CARTESIAN_POINT('',(30.0786551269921,2.43751959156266,-3.63383287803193));
#1086=CARTESIAN_POINT('',(30.2245945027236,2.63074407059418,-3.49542378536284));
#1087=CARTESIAN_POINT('',(30.4597845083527,2.89448989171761,-3.27438859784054));
#1088=CARTESIAN_POINT('',(30.5410883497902,2.97820935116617,-3.19829398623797));
#1089=CARTESIAN_POINT('',(30.7084893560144,3.13714640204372,-3.04254552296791));
#1090=CARTESIAN_POINT('',(30.794585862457,3.21236515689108,-2.96289216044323));
#1091=CARTESIAN_POINT('',(30.9985372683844,3.37667907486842,-2.77568609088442));
#1092=CARTESIAN_POINT('',(31.117922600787,3.46278578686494,-2.66717979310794));
#1093=CARTESIAN_POINT('',(31.3634116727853,3.62131961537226,-2.44761291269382));
#1094=CARTESIAN_POINT('',(31.4895211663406,3.69373476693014,-2.33655019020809));
#1095=CARTESIAN_POINT('',(31.7481871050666,3.82509253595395,-2.11461708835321));
#1096=CARTESIAN_POINT('',(31.8807275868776,3.88406663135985,-2.00374687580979));
#1097=CARTESIAN_POINT('',(32.0855541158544,3.9626628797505,-1.84048351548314));
#1098=CARTESIAN_POINT('',(32.1547928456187,3.98720677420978,-1.78659796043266));
#1099=CARTESIAN_POINT('',(32.2957288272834,4.03299263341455,-1.6806855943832));
#1100=CARTESIAN_POINT('',(32.3674253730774,4.05423553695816,-1.62865825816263));
#1101=CARTESIAN_POINT('',(32.5262601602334,4.09663441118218,-1.51920650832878));
#1102=CARTESIAN_POINT('',(32.6139628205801,4.11717103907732,-1.46235247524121));
#1103=CARTESIAN_POINT('',(32.795063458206,4.15323363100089,-1.35652326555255));
#1104=CARTESIAN_POINT('',(32.8884531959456,4.1687666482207,-1.30753704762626));
#1105=CARTESIAN_POINT('',(33.0520981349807,4.18999233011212,-1.23745182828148));
#1106=CARTESIAN_POINT('',(33.1204118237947,4.19724336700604,-1.21242591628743));
#1107=CARTESIAN_POINT('',(33.2601986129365,4.20846689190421,-1.17288093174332));
#1108=CARTESIAN_POINT('',(33.331660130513,4.21245048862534,-1.15832627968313));
#1109=CARTESIAN_POINT('',(33.47711967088,4.21672492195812,-1.14268569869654));
#1110=CARTESIAN_POINT('',(33.5511376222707,4.216971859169,-1.1417598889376));
#1111=CARTESIAN_POINT('',(33.6979183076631,4.21361799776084,-1.15406422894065));
#1112=CARTESIAN_POINT('',(33.7706787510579,4.21001080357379,-1.16731790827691));
#1113=CARTESIAN_POINT('',(33.936633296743,4.19763421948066,-1.21116542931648));
#1114=CARTESIAN_POINT('',(34.0285218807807,4.18754174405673,-1.24607641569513));
#1115=CARTESIAN_POINT('',(34.2064344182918,4.16243899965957,-1.32753495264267));
#1116=CARTESIAN_POINT('',(34.2924245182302,4.14740281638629,-1.37414350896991));
#1117=CARTESIAN_POINT('',(34.5025310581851,4.1042688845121,-1.49922761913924));
#1118=CARTESIAN_POINT('',(34.6235929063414,4.0734268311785,-1.58179027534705));
#1119=CARTESIAN_POINT('',(34.858734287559,4.00277598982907,-1.75296641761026));
#1120=CARTESIAN_POINT('',(34.9727993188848,3.96294932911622,-1.84159171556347));
#1121=CARTESIAN_POINT('',(35.1958733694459,3.87435789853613,-2.02134359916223));
#1122=CARTESIAN_POINT('',(35.3048689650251,3.82557092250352,-2.11247590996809));
#1123=CARTESIAN_POINT('',(35.5181569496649,3.71907165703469,-2.29479332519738));
#1124=CARTESIAN_POINT('',(35.6224532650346,3.6613670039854,-2.38597831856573));
#1125=CARTESIAN_POINT('',(35.8331580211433,3.53276905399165,-2.57286315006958));
#1126=CARTESIAN_POINT('',(35.9392743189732,3.46126797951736,-2.66847836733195));
#1127=CARTESIAN_POINT('',(36.1461709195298,3.30754258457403,-2.85681414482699));
#1128=CARTESIAN_POINT('',(36.2469492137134,3.22531426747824,-2.94953361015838));
#1129=CARTESIAN_POINT('',(36.5397416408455,2.96243923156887,-3.22079453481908));
#1130=CARTESIAN_POINT('',(36.7231449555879,2.7650463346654,-3.39327964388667));
#1131=CARTESIAN_POINT('',(37.0037785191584,2.39427617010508,-3.65898235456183));
#1132=CARTESIAN_POINT('',(37.1098895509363,2.23314211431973,-3.75998884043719));
#1133=CARTESIAN_POINT('',(37.3023148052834,1.88976625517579,-3.94372977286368));
#1134=CARTESIAN_POINT('',(37.388643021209,1.70753950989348,-4.02647713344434));
#1135=CARTESIAN_POINT('',(37.5248814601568,1.35390616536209,-4.15730052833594));
#1136=CARTESIAN_POINT('',(37.5783529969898,1.18515634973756,-4.20875379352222));
#1137=CARTESIAN_POINT('',(37.6427048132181,0.924795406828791,-4.27073154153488));
#1138=CARTESIAN_POINT('',(37.6615060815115,0.836859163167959,-4.28885056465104));
#1139=CARTESIAN_POINT('',(37.6935489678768,0.659069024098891,-4.31974122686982));
#1140=CARTESIAN_POINT('',(37.706793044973,0.569215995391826,-4.33251523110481));
#1141=CARTESIAN_POINT('',(37.7261772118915,0.399605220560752,-4.3512148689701));
#1142=CARTESIAN_POINT('',(37.7330005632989,0.319996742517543,-4.35779907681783));
#1143=CARTESIAN_POINT('',(37.7421127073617,0.160261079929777,-4.36659237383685));
#1144=CARTESIAN_POINT('',(37.7444004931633,0.0801337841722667,-4.36880049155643));
#1145=CARTESIAN_POINT('',(37.7444,0.,-4.3688));
#1146=B_SPLINE_CURVE_WITH_KNOTS('',3,(#998,#999,#1000,#1001,#1002,#1003,#1004,#1005,#1006,#1007,
#1008,#1009,#1010,#1011,#1012,#1013,#1014,#1015,#1016,#1017,#1018,#1019,#1020,#1021,#1022,#1023,
#1024,#1025,#1026,#1027,#1028,#1029,#1030,#1031,#1032,#1033,#1034,#1035,#1036,#1037,#1038,#1039,
#1040,#1041,#1042,#1043,#1044,#1045,#1046,#1047,#1048,#1049,#1050,#1051,#1052,#1053,#1054,#1055,
#1056,#1057,#1058,#1059,#1060,#1061,#1062,#1063,#1064,#1065,#1066,#1067,#1068,#1069,#1070,#1071,
#1072,#1073,#1074,#1075,#1076,#1077,#1078,#1079,#1080,#1081,#1082,#1083,#1084,#1085,#1086,#1087,
#1088,#1089,#1090,#1091,#1092,#1093,#1094,#1095,#1096,#1097,#1098,#1099,#1100,#1101,#1102,#1103,
#1104,#1105,#1106,#1107,#1108,#1109,#1110,#1111,#1112,#1113,#1114,#1115,#1116,#1117,#1118,#1119,
#1120,#1121,#1122,#1123,#1124,#1125,#1126,#1127,#1128,#1129,#1130,#1131,#1132,#1133,#1134,#1135,
#1136,#1137,#1138,#1139,#1140,#1141,#1142,#1143,#1144,#1145),.UNSPECIFIED.,.T.,.F.,(4,2,2,2,2,2,
2,2,2,2,2,2,2,2,2,2,2,2,2,2,2,2,2,2,2,2,2,2,2,2,2,2,2,2,2,2,2,2,2,2,2,2,2,2,2,2,2,2,2,2,2,2,2,2,
2,2,2,2,2,2,2,2,2,2,2,2,2,2,2,2,2,2,2,4),(0.,0.285694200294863,0.571531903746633,
0.857812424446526,1.14422928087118,1.71237367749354,2.28054270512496,3.08099703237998,
3.48269083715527,3.88436368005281,4.42464332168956,4.96527509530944,5.50509228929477,
6.04438731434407,6.40441343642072,6.76425446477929,7.01202702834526,7.25902787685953,
7.45392456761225,7.6485451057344,7.88493846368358,8.12251144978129,8.43318741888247,
8.74456000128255,9.05774895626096,9.37066252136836,9.9238159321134,10.4774157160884,
11.0288140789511,11.5798001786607,12.2913866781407,13.0021542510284,13.5820860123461,
13.8721992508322,14.162183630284,14.4543327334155,14.7463454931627,15.0383187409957,
15.3302665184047,15.5894268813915,15.8486716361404,16.3667261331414,16.9068458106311,
17.4471495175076,18.2789049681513,18.6965941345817,19.1142260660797,19.6621060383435,
20.2104626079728,20.7575214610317,21.0307528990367,21.303906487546,21.6231452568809,
21.9419320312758,22.1606385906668,22.3785984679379,22.5991170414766,22.8200021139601,
23.1147684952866,23.4111053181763,23.8593651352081,24.3085246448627,24.7588126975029,
25.2087172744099,25.6874205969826,26.1663027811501,27.1199913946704,27.7711688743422,
28.4218843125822,28.9723695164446,29.2472713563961,29.5220514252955,29.7623241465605,
30.0026502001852),.UNSPECIFIED.);
#1147=CARTESIAN_POINT('',(37.7444,0.,-4.3688));
#1148=VERTEX_POINT('',#1147);
#1149=EDGE_CURVE('E286',#1148,#1148,#1146,.T.);
#1150=ORIENTED_EDGE('',*,*,#1149,.T.);
#1151=EDGE_LOOP('',(#1150));
#1152=FACE_BOUND('',#1151,.T.);
#1153=ADVANCED_FACE('F129',(#976,#987,#997,#1152),#965,.F.);
#1154=CARTESIAN_POINT('',(26.9494,0.,0.));
#1155=DIRECTION('',(1.,0.,0.));
#1156=DIRECTION('',(0.,0.,-1.));
#1157=AXIS2_PLACEMENT_3D('',#1154,#1155,#1156);
#1158=PLANE('',#1157);
#1159=ORIENTED_EDGE('',*,*,#984,.F.);
#1160=EDGE_LOOP('',(#1159));
#1161=FACE_BOUND('',#1160,.T.);
#1162=ORIENTED_EDGE('',*,*,#357,.T.);
#1163=EDGE_LOOP('',(#1162));
#1164=FACE_BOUND('',#1163,.T.);
#1165=ADVANCED_FACE('F266',(#1161,#1164),#1158,.T.);
#1166=CARTESIAN_POINT('',(49.1744,0.,0.));
#1167=DIRECTION('',(1.,0.,0.));
#1168=DIRECTION('',(0.,0.,-1.));
#1169=AXIS2_PLACEMENT_3D('',#1166,#1167,#1168);
#1170=CONICAL_SURFACE('',#1169,5.0292,0.0523598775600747);
#1171=CARTESIAN_POINT('',(42.2401999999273,0.,0.));
#1172=DIRECTION('',(-1.,0.,0.));
#1173=DIRECTION('',(0.,0.,1.));
#1174=AXIS2_PLACEMENT_3D('',#1171,#1172,#1173);
#1175=CIRCLE('',#1174,4.66579397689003);
#1176=CARTESIAN_POINT('',(42.2401999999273,0.,4.66579397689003));
#1177=VERTEX_POINT('',#1176);
#1178=EDGE_CURVE('E393',#1177,#1177,#1175,.T.);
#1179=ORIENTED_EDGE('',*,*,#1178,.T.);
#1180=EDGE_LOOP('',(#1179));
#1181=FACE_BOUND('',#1180,.T.);
#1182=ORIENTED_EDGE('',*,*,#42,.F.);
#1183=EDGE_LOOP('',(#1182));
#1184=FACE_BOUND('',#1183,.T.);
#1185=ADVANCED_FACE('F397',(#1181,#1184),#1170,.F.);
#1186=CARTESIAN_POINT('',(42.2401999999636,4.3688,0.));
#1187=DIRECTION('',(1.,0.,0.));
#1188=DIRECTION('',(0.,0.,-1.));
#1189=AXIS2_PLACEMENT_3D('',#1186,#1187,#1188);
#1190=PLANE('',#1189);
#1191=ORIENTED_EDGE('',*,*,#973,.T.);
#1192=EDGE_LOOP('',(#1191));
#1193=FACE_BOUND('',#1192,.T.);
#1194=ORIENTED_EDGE('',*,*,#1178,.F.);
#1195=EDGE_LOOP('',(#1194));
#1196=FACE_BOUND('',#1195,.T.);
#1197=ADVANCED_FACE('F268',(#1193,#1196),#1190,.T.);
#1198=CARTESIAN_POINT('',(33.528,0.,-4.7625));
#1199=DIRECTION('',(0.,0.,1.));
#1200=DIRECTION('',(1.,0.,0.));
#1201=AXIS2_PLACEMENT_3D('',#1198,#1199,#1200);
#1202=CONICAL_SURFACE('',#1201,4.2164,1.02974425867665);
#1203=CARTESIAN_POINT('',(33.528,0.,-7.29596871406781));
#1204=VERTEX_POINT('',#1203);
#1205=VERTEX_LOOP('',#1204);
#1206=FACE_BOUND('',#1205,.T.);
#1207=CARTESIAN_POINT('',(33.528,0.,-4.7625));
#1208=DIRECTION('',(0.,0.,1.));
#1209=DIRECTION('',(1.,0.,0.));
#1210=AXIS2_PLACEMENT_3D('',#1207,#1208,#1209);
#1211=CIRCLE('',#1210,4.2164);
#1212=CARTESIAN_POINT('',(37.7444,0.,-4.7625));
#1213=VERTEX_POINT('',#1212);
#1214=EDGE_CURVE('E162',#1213,#1213,#1211,.T.);
#1215=ORIENTED_EDGE('',*,*,#1214,.T.);
#1216=EDGE_LOOP('',(#1215));
#1217=FACE_BOUND('',#1216,.T.);
#1218=ADVANCED_FACE('F297',(#1206,#1217),#1202,.F.);
#1219=ORIENTED_EDGE('',*,*,#1214,.F.);
#1220=EDGE_LOOP('',(#1219));
#1221=FACE_BOUND('',#1220,.T.);
#1222=ORIENTED_EDGE('',*,*,#1149,.F.);
#1223=EDGE_LOOP('',(#1222));
#1224=FACE_BOUND('',#1223,.T.);
#1225=ADVANCED_FACE('F296',(#1221,#1224),#51,.F.);
#1226=CLOSED_SHELL('',(#46,#136,#216,#244,#262,#333,#361,#415,#446,#477,#519,#550,#572,#597,
#611,#623,#839,#859,#871,#891,#903,#923,#939,#945,#960,#1153,#1165,#1185,#1197,#1218,#1225));
#1227=MANIFOLD_SOLID_BREP('B2',#1226);
#1228=ADVANCED_BREP_SHAPE_REPRESENTATION('',(#18,#1227),#14);
#1229=SHAPE_DEFINITION_REPRESENTATION(#9,#1228);
ENDSEC;
END-ISO-10303-21;
